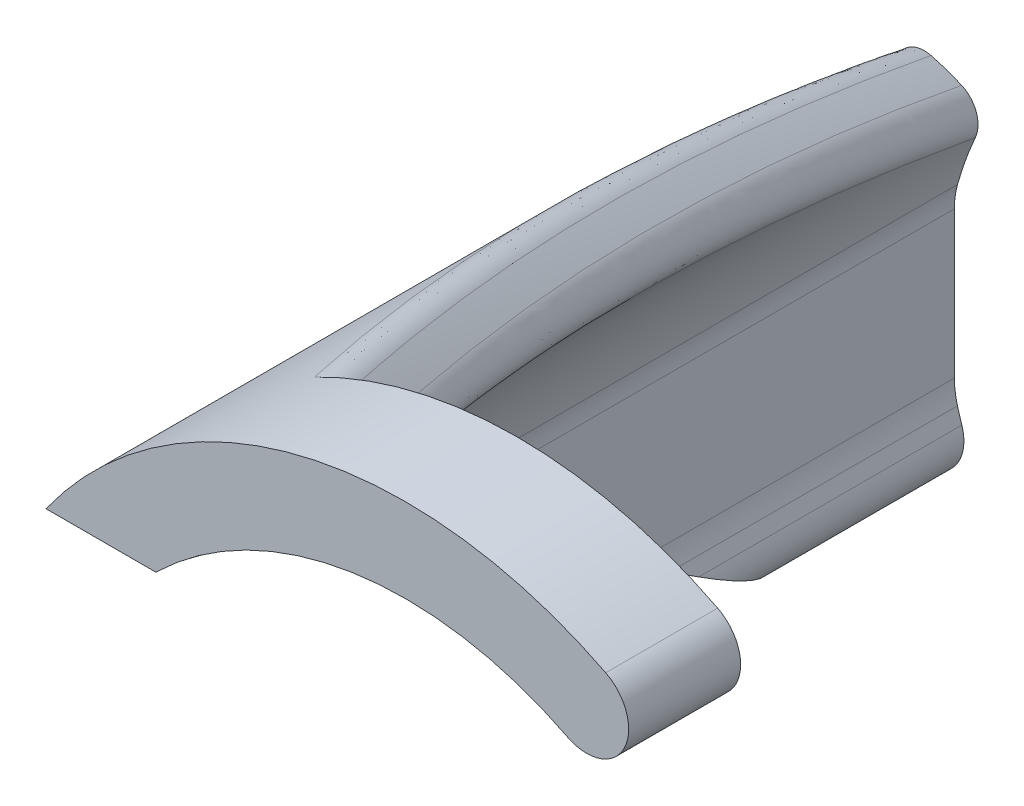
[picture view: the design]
ISO-10303-21;
HEADER;
FILE_DESCRIPTION(('STEP AP214'),'2;1');
FILE_NAME('part.step','',(''),(''),'','','');
FILE_SCHEMA(('AUTOMOTIVE_DESIGN { 1 0 10303 214 1 1 1 1 }'));
ENDSEC;
DATA;
#1=APPLICATION_CONTEXT('core data for automotive mechanical design processes');
#2=APPLICATION_PROTOCOL_DEFINITION('international standard','automotive_design',2000,#1);
#3=PRODUCT_CONTEXT('',#1,'mechanical');
#4=PRODUCT('Part','Part','',(#3));
#5=PRODUCT_RELATED_PRODUCT_CATEGORY('part','',(#4));
#6=PRODUCT_DEFINITION_FORMATION('','',#4);
#7=PRODUCT_DEFINITION_CONTEXT('part definition',#1,'design');
#8=PRODUCT_DEFINITION('design','',#6,#7);
#9=PRODUCT_DEFINITION_SHAPE('','',#8);
#10=(LENGTH_UNIT() NAMED_UNIT(*) SI_UNIT(.MILLI.,.METRE.));
#11=(NAMED_UNIT(*) PLANE_ANGLE_UNIT() SI_UNIT($,.RADIAN.));
#12=(NAMED_UNIT(*) SI_UNIT($,.STERADIAN.) SOLID_ANGLE_UNIT());
#13=UNCERTAINTY_MEASURE_WITH_UNIT(LENGTH_MEASURE(1.E-05),#10,'distance_accuracy_value','');
#14=(GEOMETRIC_REPRESENTATION_CONTEXT(3) GLOBAL_UNCERTAINTY_ASSIGNED_CONTEXT((#13)) GLOBAL_UNIT_ASSIGNED_CONTEXT((#10,
#11,#12)) REPRESENTATION_CONTEXT('',''));
#15=CARTESIAN_POINT('',(0.,0.,0.));
#16=DIRECTION('',(0.,0.,1.));
#17=DIRECTION('',(1.,0.,0.));
#18=AXIS2_PLACEMENT_3D('',#15,#16,#17);
#19=CARTESIAN_POINT('',(0.,0.,4.));
#20=DIRECTION('',(0.,0.,-1.));
#21=DIRECTION('',(-1.,0.,0.));
#22=AXIS2_PLACEMENT_3D('',#19,#20,#21);
#23=CYLINDRICAL_SURFACE('',#22,12.75);
#24=CARTESIAN_POINT('',(0.,0.,-11.774851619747));
#25=DIRECTION('',(0.,0.866025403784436,-0.500000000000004));
#26=DIRECTION('',(0.,-0.500000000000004,-0.866025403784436));
#27=AXIS2_PLACEMENT_3D('',#24,#25,#26);
#28=ELLIPSE('',#27,25.4999999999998,12.75);
#29=CARTESIAN_POINT('',(-8.92265947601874,9.10761482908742,4.));
#30=VERTEX_POINT('',#29);
#31=CARTESIAN_POINT('',(-12.2818902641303,3.42310846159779,-5.84585384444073));
#32=VERTEX_POINT('',#31);
#33=EDGE_CURVE('E165',#30,#32,#28,.F.);
#34=ORIENTED_EDGE('',*,*,#33,.T.);
#35=DIRECTION('',(0.,0.,-1.));
#36=VECTOR('',#35,1.);
#37=CARTESIAN_POINT('',(-12.2818902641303,3.42310846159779,4.));
#38=LINE('',#37,#36);
#39=CARTESIAN_POINT('',(-12.2818902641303,3.42310846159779,-28.));
#40=VERTEX_POINT('',#39);
#41=EDGE_CURVE('E379',#32,#40,#38,.T.);
#42=ORIENTED_EDGE('',*,*,#41,.T.);
#43=CARTESIAN_POINT('',(0.,0.,-28.));
#44=DIRECTION('',(0.,0.,1.));
#45=DIRECTION('',(1.,0.,0.));
#46=AXIS2_PLACEMENT_3D('',#43,#44,#45);
#47=CIRCLE('',#46,12.75);
#48=CARTESIAN_POINT('',(-11.6434217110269,5.19550102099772,-28.));
#49=VERTEX_POINT('',#48);
#50=EDGE_CURVE('E362',#40,#49,#47,.F.);
#51=ORIENTED_EDGE('',*,*,#50,.T.);
#52=CARTESIAN_POINT('',(-12.5740199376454,5.46335959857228,-31.56670425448));
#53=CARTESIAN_POINT('',(-12.2137477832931,5.30670095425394,-31.5576052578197));
#54=CARTESIAN_POINT('',(-12.0528599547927,4.95999277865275,-31.4663402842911));
#55=CARTESIAN_POINT('',(-11.8919721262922,4.61328460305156,-31.3750753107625));
#56=CARTESIAN_POINT('',(-12.0165530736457,4.26203615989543,-31.2504764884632));
#57=CARTESIAN_POINT('',(-12.5091224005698,5.65492223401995,-30.9623493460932));
#58=CARTESIAN_POINT('',(-12.1440419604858,5.49706561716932,-30.9542964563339));
#59=CARTESIAN_POINT('',(-11.9833889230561,5.14458022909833,-30.863675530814));
#60=CARTESIAN_POINT('',(-11.8225110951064,4.79266980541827,-30.7711616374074));
#61=CARTESIAN_POINT('',(-11.9539251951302,4.43858525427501,-30.6461215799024));
#62=CARTESIAN_POINT('',(-12.4391462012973,5.84425664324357,-30.3578893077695));
#63=CARTESIAN_POINT('',(-12.0698164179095,5.68464141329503,-30.3518125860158));
#64=CARTESIAN_POINT('',(-11.9096982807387,5.32687419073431,-30.2608507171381));
#65=CARTESIAN_POINT('',(-11.7493473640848,4.96963955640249,-30.168101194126));
#66=CARTESIAN_POINT('',(-11.8875210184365,4.6134826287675,-30.0416615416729));
#67=CARTESIAN_POINT('',(-12.2894975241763,6.21867938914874,-29.1488884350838));
#68=CARTESIAN_POINT('',(-11.9123950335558,6.05518332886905,-29.1465279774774));
#69=CARTESIAN_POINT('',(-11.7540277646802,5.68708166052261,-29.0550414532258));
#70=CARTESIAN_POINT('',(-11.5954236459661,5.31953410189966,-28.9617048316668));
#71=CARTESIAN_POINT('',(-11.7471739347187,4.95998040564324,-28.8326606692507));
#72=CARTESIAN_POINT('',(-12.2098250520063,6.40376772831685,-28.5443476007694));
#73=CARTESIAN_POINT('',(-11.8291931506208,6.23808584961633,-28.5438877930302));
#74=CARTESIAN_POINT('',(-11.6720478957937,5.8649951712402,-28.4520570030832));
#75=CARTESIAN_POINT('',(-11.514661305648,5.49239977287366,-28.3585297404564));
#76=CARTESIAN_POINT('',(-11.6732310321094,5.13158080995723,-28.2281198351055));
#77=CARTESIAN_POINT('',(-12.041268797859,6.76985681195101,-27.3354860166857));
#78=CARTESIAN_POINT('',(-11.6541217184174,6.59951067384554,-27.3386191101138));
#79=CARTESIAN_POINT('',(-11.4999733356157,6.21659841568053,-27.2462599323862));
#80=CARTESIAN_POINT('',(-11.3455842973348,5.83417573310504,-27.1522197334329));
#81=CARTESIAN_POINT('',(-11.5178424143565,5.47144292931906,-27.019258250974));
#82=CARTESIAN_POINT('',(-11.9523876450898,6.950858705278,-26.7311652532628));
#83=CARTESIAN_POINT('',(-11.5622467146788,6.77798805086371,-26.73610361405));
#84=CARTESIAN_POINT('',(-11.4098809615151,6.39028933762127,-26.6434473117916));
#85=CARTESIAN_POINT('',(-11.2572664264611,6.00304400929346,-26.5491979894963));
#86=CARTESIAN_POINT('',(-11.4363988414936,5.63970558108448,-26.4149374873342));
#87=CARTESIAN_POINT('',(-11.7656723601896,7.30879528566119,-25.5226635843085));
#88=CARTESIAN_POINT('',(-11.3699882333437,7.13061086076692,-25.5310844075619));
#89=CARTESIAN_POINT('',(-11.2216631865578,6.73347997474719,-25.4379345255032));
#90=CARTESIAN_POINT('',(-11.0730887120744,6.33680412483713,-25.3431866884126));
#91=CARTESIAN_POINT('',(-11.266007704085,5.97281942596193,-25.2064358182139));
#92=CARTESIAN_POINT('',(-11.6678382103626,7.48572996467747,-24.9184826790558));
#93=CARTESIAN_POINT('',(-11.269595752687,7.30471985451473,-24.928665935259));
#94=CARTESIAN_POINT('',(-11.1235377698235,6.90297968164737,-24.8352343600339));
#95=CARTESIAN_POINT('',(-10.9772218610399,6.50166180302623,-24.7402824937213));
#96=CARTESIAN_POINT('',(-11.1770601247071,6.13767061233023,-24.6022549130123));
#97=CARTESIAN_POINT('',(-11.3755205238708,7.98584177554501,-23.1906919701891));
#98=CARTESIAN_POINT('',(-10.9701603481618,7.79696139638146,-23.2038869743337));
#99=CARTESIAN_POINT('',(-10.8315106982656,7.3816710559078,-23.1116639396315));
#100=CARTESIAN_POINT('',(-10.6919623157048,6.96785485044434,-23.0141327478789));
#101=CARTESIAN_POINT('',(-10.9119416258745,6.60407378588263,-22.8744642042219));
#102=CARTESIAN_POINT('',(-11.1702905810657,8.30389578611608,-22.0673265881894));
#103=CARTESIAN_POINT('',(-10.7610991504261,8.10901153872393,-22.083833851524));
#104=CARTESIAN_POINT('',(-10.6278292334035,7.68560629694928,-21.9910252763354));
#105=CARTESIAN_POINT('',(-10.4935901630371,7.2635236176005,-21.8932136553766));
#106=CARTESIAN_POINT('',(-10.7265570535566,6.90123596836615,-21.751098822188));
#107=CARTESIAN_POINT('',(-10.730491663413,8.92436345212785,-19.8214468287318));
#108=CARTESIAN_POINT('',(-10.3146785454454,8.71688757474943,-19.8443045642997));
#109=CARTESIAN_POINT('',(-10.193346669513,8.27756871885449,-19.7506421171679));
#110=CARTESIAN_POINT('',(-10.0710428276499,7.83957197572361,-19.6519734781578));
#111=CARTESIAN_POINT('',(-10.3299578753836,7.48185059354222,-19.5052190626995));
#112=CARTESIAN_POINT('',(-10.4959146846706,9.22677280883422,-18.6989327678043));
#113=CARTESIAN_POINT('',(-10.0772302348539,9.01257370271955,-18.7250613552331));
#114=CARTESIAN_POINT('',(-9.96253817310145,8.56559152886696,-18.6308979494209));
#115=CARTESIAN_POINT('',(-9.84678817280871,8.1198195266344,-18.5318856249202));
#116=CARTESIAN_POINT('',(-10.1187362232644,7.76529926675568,-18.3827050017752));
#117=CARTESIAN_POINT('',(-9.98863708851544,9.82525693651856,-16.4127880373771));
#118=CARTESIAN_POINT('',(-9.56499845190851,9.59688269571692,-16.4453245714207));
#119=CARTESIAN_POINT('',(-9.46494474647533,9.13459376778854,-16.3505015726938));
#120=CARTESIAN_POINT('',(-9.36374599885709,8.67361377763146,-16.250431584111));
#121=CARTESIAN_POINT('',(-9.66214870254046,8.3271453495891,-16.0965602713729));
#122=CARTESIAN_POINT('',(-9.71482671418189,10.1206546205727,-15.2492153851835));
#123=CARTESIAN_POINT('',(-9.28907993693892,9.88464049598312,-15.2852130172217));
#124=CARTESIAN_POINT('',(-9.19712619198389,9.41488994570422,-15.1899113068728));
#125=CARTESIAN_POINT('',(-9.10391746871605,8.94634030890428,-15.0894478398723));
#126=CARTESIAN_POINT('',(-9.41579054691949,8.60494178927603,-14.9329876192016));
#127=CARTESIAN_POINT('',(-9.13689995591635,10.6902748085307,-12.9241721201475));
#128=CARTESIAN_POINT('',(-8.70787873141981,10.4384983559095,-12.967169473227));
#129=CARTESIAN_POINT('',(-8.63315791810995,9.95424821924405,-12.870999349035));
#130=CARTESIAN_POINT('',(-8.5571772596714,9.47120224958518,-12.7696505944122));
#131=CARTESIAN_POINT('',(-8.89569120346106,9.14159691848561,-12.6079443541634));
#132=CARTESIAN_POINT('',(-8.83278524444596,10.9644984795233,-11.7627013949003));
#133=CARTESIAN_POINT('',(-8.40247816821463,10.7044911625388,-11.8092950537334));
#134=CARTESIAN_POINT('',(-8.33700976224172,10.2133114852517,-11.7126775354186));
#135=CARTESIAN_POINT('',(-8.27015708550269,9.72323572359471,-11.6108946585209));
#136=CARTESIAN_POINT('',(-8.62195152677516,9.40045665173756,-11.4464736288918));
#137=CARTESIAN_POINT('',(-8.19488872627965,11.4890444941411,-9.44279036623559));
#138=CARTESIAN_POINT('',(-7.76295062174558,11.2121451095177,-9.49678566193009));
#139=CARTESIAN_POINT('',(-7.71696544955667,10.7075952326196,-9.39928502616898));
#140=CARTESIAN_POINT('',(-7.66959124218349,10.2041522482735,-9.29660251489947));
#141=CARTESIAN_POINT('',(-8.04748037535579,9.89669443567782,-9.12656260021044));
#142=CARTESIAN_POINT('',(-7.86112103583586,11.7393780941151,-8.28434888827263));
#143=CARTESIAN_POINT('',(-7.42870328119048,11.4537125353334,-8.34214556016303));
#144=CARTESIAN_POINT('',(-7.39308249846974,10.9428269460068,-8.24421305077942));
#145=CARTESIAN_POINT('',(-7.35593435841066,10.4329461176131,-8.14106108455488));
#146=CARTESIAN_POINT('',(-7.74676174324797,10.1340826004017,-7.96812112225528));
#147=CARTESIAN_POINT('',(-7.16416384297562,12.2134550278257,-5.9700154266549));
#148=CARTESIAN_POINT('',(-6.7317592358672,11.9098650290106,-6.03573662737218));
#149=CARTESIAN_POINT('',(-6.71782893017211,11.3868623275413,-5.93690101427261));
#150=CARTESIAN_POINT('',(-6.70236329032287,10.8648688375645,-5.83281977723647));
#151=CARTESIAN_POINT('',(-7.11843056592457,10.5848955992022,-5.65378766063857));
#152=CARTESIAN_POINT('',(-6.80096326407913,12.437188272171,-4.81412457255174));
#153=CARTESIAN_POINT('',(-6.36890443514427,12.1243283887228,-4.88392368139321));
#154=CARTESIAN_POINT('',(-6.36644796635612,11.5956559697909,-4.78466218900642));
#155=CARTESIAN_POINT('',(-6.36230293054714,11.0678818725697,-4.68007559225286));
#156=CARTESIAN_POINT('',(-6.79080789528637,10.7983113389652,-4.49789680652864));
#157=CARTESIAN_POINT('',(-6.04118170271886,12.8572289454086,-2.49184219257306));
#158=CARTESIAN_POINT('',(-5.61084251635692,12.5253800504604,-2.57021888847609));
#159=CARTESIAN_POINT('',(-5.63244895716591,11.9859337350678,-2.47007920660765));
#160=CARTESIAN_POINT('',(-5.65231717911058,11.4474111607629,-2.36445865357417));
#161=CARTESIAN_POINT('',(-6.10501027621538,11.2005044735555,-2.17561442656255));
#162=CARTESIAN_POINT('',(-5.64424747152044,13.0531683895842,-1.32549464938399));
#163=CARTESIAN_POINT('',(-5.21514791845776,12.7114576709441,-1.40835384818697));
#164=CARTESIAN_POINT('',(-5.24950205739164,12.1670535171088,-1.30778331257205));
#165=CARTESIAN_POINT('',(-5.28194266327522,11.6234421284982,-1.20161202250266));
#166=CARTESIAN_POINT('',(-5.74651129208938,11.388949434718,-1.00926688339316));
#167=CARTESIAN_POINT('',(-4.82153004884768,13.4105208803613,1.00281868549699));
#168=CARTESIAN_POINT('',(-4.39607508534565,13.0487854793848,0.910423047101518));
#169=CARTESIAN_POINT('',(-4.4568958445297,12.4952246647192,1.01198562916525));
#170=CARTESIAN_POINT('',(-4.51579362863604,11.9424595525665,1.11917599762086));
#171=CARTESIAN_POINT('',(-5.00298034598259,11.734597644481,1.31904645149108));
#172=CARTESIAN_POINT('',(-4.39574590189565,13.5719327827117,2.1647843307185));
#173=CARTESIAN_POINT('',(-3.97250912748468,13.1998865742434,2.06745825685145));
#174=CARTESIAN_POINT('',(-4.04723564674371,12.642274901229,2.16945851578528));
#175=CARTESIAN_POINT('',(-4.11984594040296,12.0853044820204,2.27724110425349));
#176=CARTESIAN_POINT('',(-4.61794750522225,11.891799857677,2.48101209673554));
#177=CARTESIAN_POINT('',(-3.51641356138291,13.8557709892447,4.48257580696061));
#178=CARTESIAN_POINT('',(-3.09891116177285,13.4628738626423,4.37467419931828));
#179=CARTESIAN_POINT('',(-3.20241901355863,12.8980438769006,4.47772214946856));
#180=CARTESIAN_POINT('',(-3.30380273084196,12.333856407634,4.58657356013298));
#181=CARTESIAN_POINT('',(-3.82228792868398,12.1708771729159,4.79880357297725));
#182=CARTESIAN_POINT('',(-3.06288450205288,13.9782238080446,5.63840528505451));
#183=CARTESIAN_POINT('',(-2.64869035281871,13.5746113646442,5.52501922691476));
#184=CARTESIAN_POINT('',(-2.76728015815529,13.0067886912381,5.62851691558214));
#185=CARTESIAN_POINT('',(-2.88353334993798,12.439422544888,5.73800562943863));
#186=CARTESIAN_POINT('',(-3.41167882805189,12.2927762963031,5.95463305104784));
#187=CARTESIAN_POINT('',(-2.12871788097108,14.1792873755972,7.9436459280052));
#188=CARTESIAN_POINT('',(-1.72261060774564,13.7540944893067,7.81840571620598));
#189=CARTESIAN_POINT('',(-1.87236283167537,13.1813107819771,7.92300839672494));
#190=CARTESIAN_POINT('',(-2.01976578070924,12.608984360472,8.03363426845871));
#191=CARTESIAN_POINT('',(-2.56543236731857,12.4968211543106,8.25987369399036));
#192=CARTESIAN_POINT('',(-1.64807812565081,14.2578945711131,9.09305656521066));
#193=CARTESIAN_POINT('',(-1.24652332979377,13.8216226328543,8.9616341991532));
#194=CARTESIAN_POINT('',(-1.41258236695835,13.2470845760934,9.06670452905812));
#195=CARTESIAN_POINT('',(-1.57605827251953,12.6727745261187,9.17801844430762));
#196=CARTESIAN_POINT('',(-2.12979298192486,12.5789636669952,9.40928433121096));
#197=CARTESIAN_POINT('',(-0.656422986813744,14.365859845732,11.3943473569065));
#198=CARTESIAN_POINT('',(-0.265693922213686,13.9073073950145,11.2494558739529));
#199=CARTESIAN_POINT('',(-0.465565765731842,13.3304481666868,11.3556518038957));
#200=CARTESIAN_POINT('',(-0.662791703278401,12.7538212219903,11.46824277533));
#201=CARTESIAN_POINT('',(-1.23050406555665,12.6986632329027,11.710575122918));
#202=CARTESIAN_POINT('',(-0.145168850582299,14.3947582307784,12.5461529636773));
#203=CARTESIAN_POINT('',(0.239501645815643,13.9247308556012,12.3941313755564));
#204=CARTESIAN_POINT('',(0.0218840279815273,13.3475891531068,12.500820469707));
#205=CARTESIAN_POINT('',(-0.192822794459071,12.770386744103,12.6141666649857));
#206=CARTESIAN_POINT('',(-0.766633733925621,12.735803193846,12.8623807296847));
#207=CARTESIAN_POINT('',(0.901885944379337,14.3946670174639,14.8392096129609));
#208=CARTESIAN_POINT('',(1.27240630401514,13.9018587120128,14.6715130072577));
#209=CARTESIAN_POINT('',(1.01823940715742,13.3256009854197,14.7794814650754));
#210=CARTESIAN_POINT('',(0.766998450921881,12.7492751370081,14.8941414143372));
#211=CARTESIAN_POINT('',(0.183849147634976,12.7575363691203,15.1554373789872));
#212=CARTESIAN_POINT('',(1.43767962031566,14.3656937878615,15.9804635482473));
#213=CARTESIAN_POINT('',(1.80039228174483,13.8612361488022,15.8044842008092));
#214=CARTESIAN_POINT('',(1.52713888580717,13.2864877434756,15.912977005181));
#215=CARTESIAN_POINT('',(1.25710226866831,12.711290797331,16.0284582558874));
#216=CARTESIAN_POINT('',(0.670455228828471,12.7421444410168,16.2966913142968));
#217=CARTESIAN_POINT('',(2.25898434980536,14.2720539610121,17.684192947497));
#218=CARTESIAN_POINT('',(2.60688374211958,13.7506468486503,17.4917892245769));
#219=CARTESIAN_POINT('',(2.30540850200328,13.1792838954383,17.6039447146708));
#220=CARTESIAN_POINT('',(2.00474613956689,12.6078117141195,17.7178667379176));
#221=CARTESIAN_POINT('',(1.4167004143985,12.6735168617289,18.0004207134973));
#222=CARTESIAN_POINT('',(2.53618825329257,14.2323638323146,18.2517288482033));
#223=CARTESIAN_POINT('',(2.8793058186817,13.7052165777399,18.0545363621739));
#224=CARTESIAN_POINT('',(2.56779012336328,13.1353407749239,18.1670306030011));
#225=CARTESIAN_POINT('',(2.25712674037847,12.5652956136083,18.2813323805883));
#226=CARTESIAN_POINT('',(1.66862614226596,12.6429575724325,18.5679566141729));
#227=CARTESIAN_POINT('',(3.09581623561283,14.1348184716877,19.3829335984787));
#228=CARTESIAN_POINT('',(3.42872641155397,13.59632235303,19.1756756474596));
#229=CARTESIAN_POINT('',(3.0968157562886,13.0299510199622,19.2889013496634));
#230=CARTESIAN_POINT('',(2.76576022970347,12.4634088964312,19.4039403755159));
#231=CARTESIAN_POINT('',(2.17733145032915,12.5653468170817,19.6991613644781));
#232=CARTESIAN_POINT('',(3.37824001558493,14.0769642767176,19.9466026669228));
#233=CARTESIAN_POINT('',(3.70576531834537,13.5327959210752,19.7341066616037));
#234=CARTESIAN_POINT('',(3.36345952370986,12.9685053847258,19.8476864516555));
#235=CARTESIAN_POINT('',(3.02204935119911,12.4039798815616,19.9631217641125));
#236=CARTESIAN_POINT('',(2.43411075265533,12.5182962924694,20.2628304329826));
#237=CARTESIAN_POINT('',(3.94814966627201,13.9415442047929,21.0700593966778));
#238=CARTESIAN_POINT('',(4.26418443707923,13.386215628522,20.8465226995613));
#239=CARTESIAN_POINT('',(3.90075807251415,12.826681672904,20.9608656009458));
#240=CARTESIAN_POINT('',(3.5382320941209,12.2669086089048,21.0770739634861));
#241=CARTESIAN_POINT('',(2.95237879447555,12.4063046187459,21.3862871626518));
#242=CARTESIAN_POINT('',(4.23564024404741,13.863958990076,21.6298426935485));
#243=CARTESIAN_POINT('',(4.54560987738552,13.303070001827,21.4005409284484));
#244=CARTESIAN_POINT('',(4.17141654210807,12.7462850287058,21.5152547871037));
#245=CARTESIAN_POINT('',(3.79816574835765,12.1891807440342,21.6318782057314));
#246=CARTESIAN_POINT('',(3.21387191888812,12.3413459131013,21.9460704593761));
#247=CARTESIAN_POINT('',(4.8148877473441,13.6873160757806,22.7443127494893));
#248=CARTESIAN_POINT('',(5.11191579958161,13.1156040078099,22.5028205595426));
#249=CARTESIAN_POINT('',(4.71586475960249,12.5649684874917,22.6183362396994));
#250=CARTESIAN_POINT('',(4.32075943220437,12.0140234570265,22.7357680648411));
#251=CARTESIAN_POINT('',(3.74084259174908,12.1919364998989,23.060540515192));
#252=CARTESIAN_POINT('',(5.1066455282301,13.5882540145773,23.2989984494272));
#253=CARTESIAN_POINT('',(5.39684005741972,13.0111953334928,23.0511211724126));
#254=CARTESIAN_POINT('',(4.98965513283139,12.4640444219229,23.1670273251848));
#255=CARTESIAN_POINT('',(4.58345815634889,11.9165118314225,23.2848931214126));
#256=CARTESIAN_POINT('',(4.00632093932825,12.1074818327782,23.6152262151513));
#257=CARTESIAN_POINT('',(5.40021582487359,13.4775744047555,23.8506943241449));
#258=CARTESIAN_POINT('',(5.68261146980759,12.8955515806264,23.5950741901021));
#259=CARTESIAN_POINT('',(5.26464476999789,12.3520607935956,23.7123820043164));
#260=CARTESIAN_POINT('',(4.84667807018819,11.8085700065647,23.8296898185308));
#261=CARTESIAN_POINT('',(4.27349910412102,12.012481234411,24.1669220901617));
#262=(BOUNDED_SURFACE() B_SPLINE_SURFACE(3,2,((#52,#53,#54,#55,#56),(#57,#58,#59,#60,#61),(#62,
#63,#64,#65,#66),(#67,#68,#69,#70,#71),(#72,#73,#74,#75,#76),(#77,#78,#79,#80,#81),(#82,#83,#84,
#85,#86),(#87,#88,#89,#90,#91),(#92,#93,#94,#95,#96),(#97,#98,#99,#100,#101),(#102,#103,#104,
#105,#106),(#107,#108,#109,#110,#111),(#112,#113,#114,#115,#116),(#117,#118,#119,#120,#121),
(#122,#123,#124,#125,#126),(#127,#128,#129,#130,#131),(#132,#133,#134,#135,#136),(#137,#138,
#139,#140,#141),(#142,#143,#144,#145,#146),(#147,#148,#149,#150,#151),(#152,#153,#154,#155,
#156),(#157,#158,#159,#160,#161),(#162,#163,#164,#165,#166),(#167,#168,#169,#170,#171),(#172,
#173,#174,#175,#176),(#177,#178,#179,#180,#181),(#182,#183,#184,#185,#186),(#187,#188,#189,#190,
#191),(#192,#193,#194,#195,#196),(#197,#198,#199,#200,#201),(#202,#203,#204,#205,#206),(#207,
#208,#209,#210,#211),(#212,#213,#214,#215,#216),(#217,#218,#219,#220,#221),(#222,#223,#224,#225,
#226),(#227,#228,#229,#230,#231),(#232,#233,#234,#235,#236),(#237,#238,#239,#240,#241),(#242,
#243,#244,#245,#246),(#247,#248,#249,#250,#251),(#252,#253,#254,#255,#256),(#257,#258,#259,#260,
#261)),.UNSPECIFIED.,.F.,.F.,.F.) B_SPLINE_SURFACE_WITH_KNOTS((4,2,2,2,2,2,2,2,2,2,2,2,2,2,2,2,
2,2,2,2,4),(3,2,3),(0.,1.91166132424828,3.82332152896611,5.73443742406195,7.64555709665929,
11.2006112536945,14.7566371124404,18.4477547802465,22.1386688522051,25.8278351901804,
29.518396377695,33.2539924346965,36.9897122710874,40.7228842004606,44.4563586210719,
48.2241772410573,51.9909302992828,53.8809245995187,55.770811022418,57.6625568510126,
59.5546872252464),(0.,0.5,1.),
.UNSPECIFIED.) GEOMETRIC_REPRESENTATION_ITEM() RATIONAL_B_SPLINE_SURFACE(((1.,0.930717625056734,
1.,0.930717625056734,1.),(1.,0.929178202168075,1.,0.929178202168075,1.),(1.,0.927719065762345,
1.,0.927719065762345,1.),(1.,0.924924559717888,1.,0.924924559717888,1.),(1.,0.923589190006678,
1.,0.923589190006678,1.),(1.,0.921005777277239,1.,0.921005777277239,1.),(1.,0.919757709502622,
1.,0.919757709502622,1.),(1.,0.917326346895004,1.,0.917326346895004,1.),(1.,0.916143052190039,
1.,0.916143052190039,1.),(1.,0.912826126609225,1.,0.912826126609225,1.),(1.,0.910750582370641,
1.,0.910750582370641,1.),(1.,0.906690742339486,1.,0.906690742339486,1.),(1.,0.904706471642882,
1.,0.904706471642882,1.),(1.,0.900711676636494,1.,0.900711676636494,1.),(1.,0.898703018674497,
1.,0.898703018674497,1.),(1.,0.894704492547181,1.,0.894704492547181,1.),(1.,0.892714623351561,
1.,0.892714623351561,1.),(1.,0.88873065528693,1.,0.88873065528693,1.),(1.,0.886736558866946,1.,
0.886736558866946,1.),(1.,0.882723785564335,1.,0.882723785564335,1.),(1.,0.880705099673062,1.,
0.880705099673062,1.),(1.,0.876603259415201,1.,0.876603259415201,1.),(1.,0.874519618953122,1.,
0.874519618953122,1.),(1.,0.870296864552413,1.,0.870296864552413,1.),(1.,0.868157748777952,1.,
0.868157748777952,1.),(1.,0.863811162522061,1.,0.863811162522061,1.),(1.,0.861603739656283,1.,
0.861603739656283,1.),(1.,0.857104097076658,1.,0.857104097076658,1.),(1.,0.854811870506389,1.,
0.854811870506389,1.),(1.,0.850105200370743,1.,0.850105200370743,1.),(1.,0.847689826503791,1.,
0.847689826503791,1.),(1.,0.842738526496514,1.,0.842738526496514,1.),(1.,0.840202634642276,1.,
0.840202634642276,1.),(1.,0.836287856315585,1.,0.836287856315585,1.),(1.,0.834962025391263,1.,
0.834962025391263,1.),(1.,0.832271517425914,1.,0.832271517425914,1.),(1.,0.830906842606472,1.,
0.830906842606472,1.),(1.,0.828134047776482,1.,0.828134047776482,1.),(1.,0.826725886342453,1.,
0.826725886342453,1.),(1.,0.823863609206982,1.,0.823863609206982,1.),(1.,0.822409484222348,1.,
0.822409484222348,1.),(1.,0.820930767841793,1.,0.820930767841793,1.))) REPRESENTATION_ITEM('') SURFACE());
#263=CARTESIAN_POINT('',(-12.0165530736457,4.26203615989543,-31.2504764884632));
#264=CARTESIAN_POINT('',(-11.9539251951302,4.43858525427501,-30.6461215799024));
#265=CARTESIAN_POINT('',(-11.8875210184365,4.6134826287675,-30.0416615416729));
#266=CARTESIAN_POINT('',(-11.7471739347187,4.95998040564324,-28.8326606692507));
#267=CARTESIAN_POINT('',(-11.6732310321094,5.13158080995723,-28.2281198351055));
#268=CARTESIAN_POINT('',(-11.5178424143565,5.47144292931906,-27.019258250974));
#269=CARTESIAN_POINT('',(-11.4363988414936,5.63970558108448,-26.4149374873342));
#270=CARTESIAN_POINT('',(-11.266007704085,5.97281942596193,-25.2064358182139));
#271=CARTESIAN_POINT('',(-11.1770601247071,6.13767061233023,-24.6022549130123));
#272=CARTESIAN_POINT('',(-10.9119416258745,6.60407378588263,-22.8744642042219));
#273=CARTESIAN_POINT('',(-10.7265570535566,6.90123596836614,-21.751098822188));
#274=CARTESIAN_POINT('',(-10.3299578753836,7.48185059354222,-19.5052190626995));
#275=CARTESIAN_POINT('',(-10.1187362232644,7.76529926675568,-18.3827050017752));
#276=CARTESIAN_POINT('',(-9.66214870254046,8.3271453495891,-16.0965602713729));
#277=CARTESIAN_POINT('',(-9.41579054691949,8.60494178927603,-14.9329876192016));
#278=CARTESIAN_POINT('',(-8.89569120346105,9.14159691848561,-12.6079443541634));
#279=CARTESIAN_POINT('',(-8.62195152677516,9.40045665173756,-11.4464736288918));
#280=CARTESIAN_POINT('',(-8.04748037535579,9.89669443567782,-9.12656260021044));
#281=CARTESIAN_POINT('',(-7.74676174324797,10.1340826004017,-7.96812112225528));
#282=CARTESIAN_POINT('',(-7.11843056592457,10.5848955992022,-5.65378766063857));
#283=CARTESIAN_POINT('',(-6.79080789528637,10.7983113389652,-4.49789680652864));
#284=CARTESIAN_POINT('',(-6.10501027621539,11.2005044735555,-2.17561442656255));
#285=CARTESIAN_POINT('',(-5.74651129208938,11.388949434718,-1.00926688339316));
#286=CARTESIAN_POINT('',(-5.00298034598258,11.734597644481,1.31904645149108));
#287=CARTESIAN_POINT('',(-4.61794750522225,11.891799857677,2.48101209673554));
#288=CARTESIAN_POINT('',(-3.82228792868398,12.1708771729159,4.79880357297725));
#289=CARTESIAN_POINT('',(-3.41167882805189,12.2927762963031,5.95463305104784));
#290=CARTESIAN_POINT('',(-2.56543236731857,12.4968211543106,8.25987369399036));
#291=CARTESIAN_POINT('',(-2.12979298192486,12.5789636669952,9.40928433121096));
#292=CARTESIAN_POINT('',(-1.23050406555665,12.6986632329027,11.710575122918));
#293=CARTESIAN_POINT('',(-0.766633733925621,12.735803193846,12.8623807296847));
#294=CARTESIAN_POINT('',(0.183849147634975,12.7575363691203,15.1554373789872));
#295=CARTESIAN_POINT('',(0.670455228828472,12.7421444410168,16.2966913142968));
#296=CARTESIAN_POINT('',(1.4167004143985,12.6735168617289,18.0004207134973));
#297=CARTESIAN_POINT('',(1.66862614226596,12.6429575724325,18.5679566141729));
#298=CARTESIAN_POINT('',(2.17733145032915,12.5653468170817,19.6991613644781));
#299=CARTESIAN_POINT('',(2.43411075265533,12.5182962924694,20.2628304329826));
#300=CARTESIAN_POINT('',(2.95237879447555,12.4063046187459,21.3862871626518));
#301=CARTESIAN_POINT('',(3.21387191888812,12.3413459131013,21.9460704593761));
#302=CARTESIAN_POINT('',(3.74084259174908,12.1919364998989,23.060540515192));
#303=CARTESIAN_POINT('',(4.00632093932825,12.1074818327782,23.6152262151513));
#304=CARTESIAN_POINT('',(4.27349910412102,12.012481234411,24.1669220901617));
#305=B_SPLINE_CURVE_WITH_KNOTS('',3,(#263,#264,#265,#266,#267,#268,#269,#270,#271,#272,#273,
#274,#275,#276,#277,#278,#279,#280,#281,#282,#283,#284,#285,#286,#287,#288,#289,#290,#291,#292,
#293,#294,#295,#296,#297,#298,#299,#300,#301,#302,#303,#304),.UNSPECIFIED.,.F.,.F.,(4,2,2,2,2,2,
2,2,2,2,2,2,2,2,2,2,2,2,2,2,4),(0.,1.91166132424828,3.82332152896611,5.73443742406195,
7.64555709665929,11.2006112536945,14.7566371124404,18.4477547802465,22.1386688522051,
25.8278351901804,29.518396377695,33.2539924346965,36.9897122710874,40.7228842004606,
44.4563586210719,48.2241772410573,51.9909302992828,53.8809245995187,55.770811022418,
57.6625568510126,59.5546872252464),.UNSPECIFIED.);
#306=CARTESIAN_POINT('',(-5.42412642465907,11.538689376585,0.));
#307=VERTEX_POINT('',#306);
#308=EDGE_CURVE('E298',#49,#307,#305,.T.);
#309=ORIENTED_EDGE('',*,*,#308,.T.);
#310=CARTESIAN_POINT('',(0.,0.,0.));
#311=DIRECTION('',(0.,0.,1.));
#312=DIRECTION('',(1.,0.,0.));
#313=AXIS2_PLACEMENT_3D('',#310,#311,#312);
#314=CIRCLE('',#313,12.75);
#315=CARTESIAN_POINT('',(5.78837887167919,11.3603331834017,0.));
#316=VERTEX_POINT('',#315);
#317=EDGE_CURVE('E190',#307,#316,#314,.F.);
#318=ORIENTED_EDGE('',*,*,#317,.T.);
#319=DIRECTION('',(0.,0.,-1.));
#320=VECTOR('',#319,1.);
#321=CARTESIAN_POINT('',(5.78837887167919,11.3603331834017,4.));
#322=LINE('',#321,#320);
#323=CARTESIAN_POINT('',(5.78837887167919,11.3603331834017,4.));
#324=VERTEX_POINT('',#323);
#325=EDGE_CURVE('E202',#324,#316,#322,.T.);
#326=ORIENTED_EDGE('',*,*,#325,.F.);
#327=CARTESIAN_POINT('',(0.,0.,4.));
#328=DIRECTION('',(0.,0.,1.));
#329=DIRECTION('',(1.,0.,0.));
#330=AXIS2_PLACEMENT_3D('',#327,#328,#329);
#331=CIRCLE('',#330,12.75);
#332=EDGE_CURVE('E185',#30,#324,#331,.F.);
#333=ORIENTED_EDGE('',*,*,#332,.F.);
#334=EDGE_LOOP('',(#34,#42,#51,#309,#318,#326,#333));
#335=FACE_BOUND('',#334,.T.);
#336=ADVANCED_FACE('F41',(#335),#23,.F.);
#337=CARTESIAN_POINT('',(0.,0.,4.));
#338=DIRECTION('',(0.,0.,-1.));
#339=DIRECTION('',(-1.,0.,0.));
#340=AXIS2_PLACEMENT_3D('',#337,#338,#339);
#341=CYLINDRICAL_SURFACE('',#340,15.75);
#342=CARTESIAN_POINT('',(0.,0.,-28.));
#343=DIRECTION('',(0.,0.,1.));
#344=DIRECTION('',(1.,0.,0.));
#345=AXIS2_PLACEMENT_3D('',#342,#343,#344);
#346=CIRCLE('',#345,15.75);
#347=CARTESIAN_POINT('',(-14.765625,5.48076804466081,-28.));
#348=VERTEX_POINT('',#347);
#349=CARTESIAN_POINT('',(-14.422335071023,6.32919829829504,-28.));
#350=VERTEX_POINT('',#349);
#351=EDGE_CURVE('E354',#348,#350,#346,.F.);
#352=ORIENTED_EDGE('',*,*,#351,.F.);
#353=DIRECTION('',(0.,0.,-1.));
#354=VECTOR('',#353,1.);
#355=CARTESIAN_POINT('',(-14.765625,5.48076804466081,4.));
#356=LINE('',#355,#354);
#357=CARTESIAN_POINT('',(-14.765625,5.4807680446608,-2.28188290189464));
#358=VERTEX_POINT('',#357);
#359=EDGE_CURVE('E178',#348,#358,#356,.F.);
#360=ORIENTED_EDGE('',*,*,#359,.T.);
#361=CARTESIAN_POINT('',(0.,0.,-11.774851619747));
#362=DIRECTION('',(0.,0.866025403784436,-0.500000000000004));
#363=DIRECTION('',(0.,-0.500000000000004,-0.866025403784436));
#364=AXIS2_PLACEMENT_3D('',#361,#362,#363);
#365=ELLIPSE('',#364,31.4999999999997,15.75);
#366=CARTESIAN_POINT('',(-12.849663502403,9.10761482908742,4.));
#367=VERTEX_POINT('',#366);
#368=EDGE_CURVE('E163',#367,#358,#365,.F.);
#369=ORIENTED_EDGE('',*,*,#368,.F.);
#370=CARTESIAN_POINT('',(0.,0.,4.));
#371=DIRECTION('',(0.,0.,1.));
#372=DIRECTION('',(1.,0.,0.));
#373=AXIS2_PLACEMENT_3D('',#370,#371,#372);
#374=CIRCLE('',#373,15.75);
#375=CARTESIAN_POINT('',(7.15035037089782,14.0333527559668,4.));
#376=VERTEX_POINT('',#375);
#377=EDGE_CURVE('E175',#367,#376,#374,.F.);
#378=ORIENTED_EDGE('',*,*,#377,.T.);
#379=DIRECTION('',(0.,0.,-1.));
#380=VECTOR('',#379,1.);
#381=CARTESIAN_POINT('',(7.15035037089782,14.0333527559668,4.));
#382=LINE('',#381,#380);
#383=CARTESIAN_POINT('',(7.15035037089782,14.0333527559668,0.));
#384=VERTEX_POINT('',#383);
#385=EDGE_CURVE('E197',#376,#384,#382,.T.);
#386=ORIENTED_EDGE('',*,*,#385,.T.);
#387=CARTESIAN_POINT('',(0.,0.,0.));
#388=DIRECTION('',(0.,0.,1.));
#389=DIRECTION('',(1.,0.,0.));
#390=AXIS2_PLACEMENT_3D('',#387,#388,#389);
#391=CIRCLE('',#390,15.75);
#392=CARTESIAN_POINT('',(-7.26053441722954,13.9766641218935,0.));
#393=VERTEX_POINT('',#392);
#394=EDGE_CURVE('E198',#393,#384,#391,.F.);
#395=ORIENTED_EDGE('',*,*,#394,.F.);
#396=CARTESIAN_POINT('',(-15.1270251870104,4.38584187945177,-33.7644915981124));
#397=CARTESIAN_POINT('',(-14.8827218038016,5.22845853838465,-34.0579170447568));
#398=CARTESIAN_POINT('',(-13.9779277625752,5.03711260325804,-34.0807193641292));
#399=CARTESIAN_POINT('',(-15.0591973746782,4.61977963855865,-33.0824569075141));
#400=CARTESIAN_POINT('',(-14.8048072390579,5.44873859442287,-33.3761714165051));
#401=CARTESIAN_POINT('',(-13.9102353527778,5.25535257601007,-33.3986846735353));
#402=CARTESIAN_POINT('',(-14.9858608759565,4.8524347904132,-32.4005280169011));
#403=CARTESIAN_POINT('',(-14.7213676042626,5.66910088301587,-32.6914414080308));
#404=CARTESIAN_POINT('',(-13.8369452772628,5.47226977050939,-32.7167557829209));
#405=CARTESIAN_POINT('',(-14.8281846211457,5.31480136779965,-31.0369058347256));
#406=CARTESIAN_POINT('',(-14.5441115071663,6.10708665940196,-31.3229262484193));
#407=CARTESIAN_POINT('',(-13.6794196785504,5.90312590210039,-31.3531336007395));
#408=CARTESIAN_POINT('',(-14.7438447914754,5.54451277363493,-30.3552125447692));
#409=CARTESIAN_POINT('',(-14.4503220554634,6.32488722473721,-30.6386532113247));
#410=CARTESIAN_POINT('',(-13.5951840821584,6.11706481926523,-30.6714403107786));
#411=CARTESIAN_POINT('',(-14.4743204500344,6.2287160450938,-28.3103650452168));
#412=CARTESIAN_POINT('',(-14.1545761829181,6.97073899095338,-28.5952228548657));
#413=CARTESIAN_POINT('',(-13.3264128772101,6.75396391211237,-28.6265928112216));
#414=CARTESIAN_POINT('',(-14.2726480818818,6.67821817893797,-26.9476140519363));
#415=CARTESIAN_POINT('',(-13.936112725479,7.39708534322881,-27.2274055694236));
#416=CARTESIAN_POINT('',(-13.125829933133,7.17195159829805,-27.26384181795));
#417=CARTESIAN_POINT('',(-13.8259020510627,7.55981121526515,-24.225881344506));
#418=CARTESIAN_POINT('',(-13.4581466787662,8.23162302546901,-24.4978819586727));
#419=CARTESIAN_POINT('',(-12.6832114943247,7.99087232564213,-24.5421091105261));
#420=CARTESIAN_POINT('',(-13.5808987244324,7.99192896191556,-22.8668970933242));
#421=CARTESIAN_POINT('',(-13.1990508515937,8.6405010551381,-23.1347581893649));
#422=CARTESIAN_POINT('',(-12.4412431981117,8.39183171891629,-23.1831248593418));
#423=CARTESIAN_POINT('',(-13.047532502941,8.83592444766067,-20.1510011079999));
#424=CARTESIAN_POINT('',(-12.6398216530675,9.43732629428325,-20.4120720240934));
#425=CARTESIAN_POINT('',(-11.9162215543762,9.17404272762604,-20.467228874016));
#426=CARTESIAN_POINT('',(-12.7591745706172,9.24780449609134,-18.7940891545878));
#427=CARTESIAN_POINT('',(-12.3400340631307,9.82581213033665,-19.0515518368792));
#428=CARTESIAN_POINT('',(-11.6331729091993,9.55529659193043,-19.1103169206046));
#429=CARTESIAN_POINT('',(-12.3068919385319,9.83142681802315,-16.8154399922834));
#430=CARTESIAN_POINT('',(-11.8712308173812,10.3766803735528,-17.0619019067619));
#431=CARTESIAN_POINT('',(-11.190420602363,10.09476886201,-17.1316677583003));
#432=CARTESIAN_POINT('',(-12.1599418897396,10.0126479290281,-16.19270979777));
#433=CARTESIAN_POINT('',(-11.719865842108,10.5470292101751,-16.4377860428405));
#434=CARTESIAN_POINT('',(-11.0467289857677,10.262168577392,-16.5089375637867));
#435=CARTESIAN_POINT('',(-11.85693763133,10.3696850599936,-14.9476154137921));
#436=CARTESIAN_POINT('',(-11.4085615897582,10.8822696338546,-15.1900372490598));
#437=CARTESIAN_POINT('',(-10.7507667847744,10.5917394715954,-15.2638431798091));
#438=CARTESIAN_POINT('',(-11.7008806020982,10.545499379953,-14.3252513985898));
#439=CARTESIAN_POINT('',(-11.248651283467,11.0472054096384,-14.5663416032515));
#440=CARTESIAN_POINT('',(-10.5984935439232,10.7539090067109,-14.6414791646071));
#441=CARTESIAN_POINT('',(-11.2041957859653,11.0802730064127,-12.4010614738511));
#442=CARTESIAN_POINT('',(-10.7423425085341,11.5468212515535,-12.64380239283));
#443=CARTESIAN_POINT('',(-10.114336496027,11.2467899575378,-12.7172892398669));
#444=CARTESIAN_POINT('',(-10.848298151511,11.4293314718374,-11.1002321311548));
#445=CARTESIAN_POINT('',(-10.3803022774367,11.8733031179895,-11.3401490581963));
#446=CARTESIAN_POINT('',(-9.76808334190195,11.5679432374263,-11.416459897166));
#447=CARTESIAN_POINT('',(-10.0973710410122,12.0978643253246,-8.5017846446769));
#448=CARTESIAN_POINT('',(-9.61927080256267,12.4964679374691,-8.73671055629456));
#449=CARTESIAN_POINT('',(-9.03881728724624,12.181768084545,-8.81801241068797));
#450=CARTESIAN_POINT('',(-9.7023406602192,12.4173380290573,-7.20416657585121));
#451=CARTESIAN_POINT('',(-9.2205538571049,12.7935583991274,-7.43649254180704));
#452=CARTESIAN_POINT('',(-8.6558035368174,12.4744389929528,-7.52039434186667));
#453=CARTESIAN_POINT('',(-8.87380983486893,13.0223284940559,-4.61322147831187));
#454=CARTESIAN_POINT('',(-8.38683478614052,13.3537501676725,-4.84091254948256));
#455=CARTESIAN_POINT('',(-7.85368529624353,13.0271612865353,-4.92944924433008));
#456=CARTESIAN_POINT('',(-8.44032211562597,13.3078564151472,-3.3198931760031));
#457=CARTESIAN_POINT('',(-7.95210540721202,13.6172771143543,-3.54517061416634));
#458=CARTESIAN_POINT('',(-7.43459274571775,13.2872233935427,-3.63612094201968));
#459=CARTESIAN_POINT('',(-7.53530797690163,13.8404260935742,-0.737575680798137));
#460=CARTESIAN_POINT('',(-7.04679243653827,14.1059875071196,-0.958538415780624));
#461=CARTESIAN_POINT('',(-6.56074783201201,13.7704275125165,-1.05380344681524));
#462=CARTESIAN_POINT('',(-7.06377311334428,14.0874592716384,0.551412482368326));
#463=CARTESIAN_POINT('',(-6.57644185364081,14.3315932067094,0.332705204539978));
#464=CARTESIAN_POINT('',(-6.10598755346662,13.9935612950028,0.235184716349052));
#465=CARTESIAN_POINT('',(-6.21510538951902,14.4772454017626,2.77861358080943));
#466=CARTESIAN_POINT('',(-5.73064730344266,14.6850192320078,2.56621875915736));
#467=CARTESIAN_POINT('',(-5.28840379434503,14.3435560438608,2.46238581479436));
#468=CARTESIAN_POINT('',(-5.84658779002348,14.6301940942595,3.71815198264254));
#469=CARTESIAN_POINT('',(-5.36448528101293,14.8227176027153,3.5072536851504));
#470=CARTESIAN_POINT('',(-4.93364947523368,14.4801847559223,3.40192421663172));
#471=CARTESIAN_POINT('',(-5.09007787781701,14.9102755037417,5.59376497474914));
#472=CARTESIAN_POINT('',(-4.61388205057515,15.0726335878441,5.38566476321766));
#473=CARTESIAN_POINT('',(-4.20591017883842,14.7287268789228,5.27753720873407));
#474=CARTESIAN_POINT('',(-4.70208528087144,15.0374078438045,6.52983951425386));
#475=CARTESIAN_POINT('',(-4.22952113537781,15.1850349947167,6.32316945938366));
#476=CARTESIAN_POINT('',(-3.83292493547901,14.8406399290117,6.21361174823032));
#477=CARTESIAN_POINT('',(-3.90726374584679,15.2632375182,8.39759312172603));
#478=CARTESIAN_POINT('',(-3.4431465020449,15.3818377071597,8.19359577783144));
#479=CARTESIAN_POINT('',(-3.06933568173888,15.037263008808,8.08136535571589));
#480=CARTESIAN_POINT('',(-3.50044174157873,15.3619452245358,9.32927367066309));
#481=CARTESIAN_POINT('',(-3.0412137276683,15.4664414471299,9.12664478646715));
#482=CARTESIAN_POINT('',(-2.67873815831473,15.1219829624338,9.01304590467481));
#483=CARTESIAN_POINT('',(-2.66843345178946,15.52810137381,11.1878683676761));
#484=CARTESIAN_POINT('',(-2.22015657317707,15.6049190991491,10.9877901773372));
#485=CARTESIAN_POINT('',(-1.88037389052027,15.2615280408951,10.8716406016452));
#486=CARTESIAN_POINT('',(-2.24324773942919,15.5955507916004,12.1147826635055));
#487=CARTESIAN_POINT('',(-1.80109846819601,15.6589960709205,11.9160161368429));
#488=CARTESIAN_POINT('',(-1.47260768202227,15.3163540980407,11.7985548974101));
#489=CARTESIAN_POINT('',(-1.37281047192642,15.6962073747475,13.9681733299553));
#490=CARTESIAN_POINT('',(-0.944124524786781,15.7334718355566,13.7718192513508));
#491=CARTESIAN_POINT('',(-0.638270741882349,15.3932158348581,13.6519455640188));
#492=CARTESIAN_POINT('',(-0.927460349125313,15.7292217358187,14.8946185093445));
#493=CARTESIAN_POINT('',(-0.506159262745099,15.7538988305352,14.6995315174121));
#494=CARTESIAN_POINT('',(-0.211607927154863,15.4150671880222,14.578390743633));
#495=CARTESIAN_POINT('',(-0.0199101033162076,15.7565288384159,16.7406412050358));
#496=CARTESIAN_POINT('',(0.385476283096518,15.7567986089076,16.5478969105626));
#497=CARTESIAN_POINT('',(0.657441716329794,15.421761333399,16.4244134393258));
#498=CARTESIAN_POINT('',(0.442287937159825,15.7508263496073,17.6602195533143));
#499=CARTESIAN_POINT('',(0.839097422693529,15.7395056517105,17.4686925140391));
#500=CARTESIAN_POINT('',(1.09982660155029,15.4066086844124,17.3439917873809));
#501=CARTESIAN_POINT('',(1.38326814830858,15.6962298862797,19.4929142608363));
#502=CARTESIAN_POINT('',(1.76178750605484,15.6626104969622,19.3036182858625));
#503=CARTESIAN_POINT('',(2.00007345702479,15.3350094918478,19.1766864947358));
#504=CARTESIAN_POINT('',(1.86207850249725,15.6472586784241,20.4060161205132));
#505=CARTESIAN_POINT('',(2.23085295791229,15.6031775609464,20.2178955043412));
#506=CARTESIAN_POINT('',(2.45796169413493,15.2784891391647,20.0897883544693));
#507=CARTESIAN_POINT('',(2.59100962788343,15.5373594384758,21.7682555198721));
#508=CARTESIAN_POINT('',(2.94538052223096,15.4781982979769,21.5836992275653));
#509=CARTESIAN_POINT('',(3.15476073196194,15.1588826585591,21.4520277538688));
#510=CARTESIAN_POINT('',(2.83583295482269,15.4946379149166,22.221208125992));
#511=CARTESIAN_POINT('',(3.18491939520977,15.4306905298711,22.0371892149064));
#512=CARTESIAN_POINT('',(3.3887458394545,15.1131942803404,21.9049803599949));
#513=CARTESIAN_POINT('',(3.32879853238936,15.3962558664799,23.1243318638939));
#514=CARTESIAN_POINT('',(3.66704854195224,15.3230536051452,22.9413523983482));
#515=CARTESIAN_POINT('',(3.85979797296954,15.0094522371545,22.8081040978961));
#516=CARTESIAN_POINT('',(3.57694105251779,15.3405942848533,23.5745027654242));
#517=CARTESIAN_POINT('',(3.90963807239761,15.262957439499,23.3920476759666));
#518=CARTESIAN_POINT('',(4.09686524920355,14.9513975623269,23.2582749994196));
#519=CARTESIAN_POINT('',(3.82661451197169,15.2780732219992,24.0231283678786));
#520=CARTESIAN_POINT('',(4.15397181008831,15.19608184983,23.8418093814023));
#521=CARTESIAN_POINT('',(4.33535141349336,14.8867874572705,23.7069006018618));
#522=(BOUNDED_SURFACE() B_SPLINE_SURFACE(3,2,((#396,#397,#398),(#399,#400,#401),(#402,#403,
#404),(#405,#406,#407),(#408,#409,#410),(#411,#412,#413),(#414,#415,#416),(#417,#418,#419),
(#420,#421,#422),(#423,#424,#425),(#426,#427,#428),(#429,#430,#431),(#432,#433,#434),(#435,#436,
#437),(#438,#439,#440),(#441,#442,#443),(#444,#445,#446),(#447,#448,#449),(#450,#451,#452),
(#453,#454,#455),(#456,#457,#458),(#459,#460,#461),(#462,#463,#464),(#465,#466,#467),(#468,#469,
#470),(#471,#472,#473),(#474,#475,#476),(#477,#478,#479),(#480,#481,#482),(#483,#484,#485),
(#486,#487,#488),(#489,#490,#491),(#492,#493,#494),(#495,#496,#497),(#498,#499,#500),(#501,#502,
#503),(#504,#505,#506),(#507,#508,#509),(#510,#511,#512),(#513,#514,#515),(#516,#517,#518),
(#519,#520,#521)),.UNSPECIFIED.,.F.,.F.,.F.) B_SPLINE_SURFACE_WITH_KNOTS((4,2,2,2,2,2,2,2,2,2,2,
2,2,2,2,2,2,2,2,2,4),(3,3),(0.,2.15746623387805,4.31494689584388,8.63044860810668,
12.9390085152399,17.2470756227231,19.2268658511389,21.2072723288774,25.352675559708,
29.498174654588,33.6423071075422,37.7873618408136,40.8203001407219,43.853282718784,
46.8851571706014,49.9169370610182,52.9656024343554,56.0138922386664,59.0676341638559,
60.5952423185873,62.1229752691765),(0.,1.),
.UNSPECIFIED.) GEOMETRIC_REPRESENTATION_ITEM() RATIONAL_B_SPLINE_SURFACE(((1.,0.734067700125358,
1.),(1.,0.737601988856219,1.),(1.,0.740959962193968,1.),(1.,0.747412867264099,1.),(1.,
0.750507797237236,1.),(1.,0.759533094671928,1.),(1.,0.765203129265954,1.),(1.,0.776135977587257,
1.),(1.,0.781399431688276,1.),(1.,0.791657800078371,1.),(1.,0.796652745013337,1.),(1.,
0.803798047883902,1.),(1.,0.806026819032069,1.),(1.,0.810447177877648,1.),(1.,0.812638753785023,
1.),(1.,0.81936518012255,1.),(1.,0.823842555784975,1.),(1.,0.832671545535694,1.),(1.,
0.83702315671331,1.),(1.,0.845614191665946,1.),(1.,0.849853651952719,1.),(1.,0.858232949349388,
1.),(1.,0.862372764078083,1.),(1.,0.869459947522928,1.),(1.,0.872429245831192,1.),(1.,
0.878319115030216,1.),(1.,0.881239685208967,1.),(1.,0.887031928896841,1.),(1.,0.889903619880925,
1.),(1.,0.895599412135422,1.),(1.,0.898423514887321,1.),(1.,0.904039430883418,1.),(1.,
0.906830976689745,1.),(1.,0.912364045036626,1.),(1.,0.915105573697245,1.),(1.,0.920541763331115,
1.),(1.,0.923236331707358,1.),(1.,0.927236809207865,1.),(1.,0.928563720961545,1.),(1.,
0.931203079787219,1.),(1.,0.932515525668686,1.),(1.,0.933820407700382,1.))) REPRESENTATION_ITEM('') SURFACE());
#523=CARTESIAN_POINT('',(3.82661451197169,15.2780732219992,24.0231283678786));
#524=CARTESIAN_POINT('',(3.57694105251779,15.3405942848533,23.5745027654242));
#525=CARTESIAN_POINT('',(3.32879853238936,15.3962558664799,23.1243318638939));
#526=CARTESIAN_POINT('',(2.83583295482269,15.4946379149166,22.221208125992));
#527=CARTESIAN_POINT('',(2.59100962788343,15.5373594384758,21.7682555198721));
#528=CARTESIAN_POINT('',(1.86207850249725,15.6472586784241,20.4060161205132));
#529=CARTESIAN_POINT('',(1.38326814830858,15.6962298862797,19.4929142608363));
#530=CARTESIAN_POINT('',(0.442287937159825,15.7508263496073,17.6602195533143));
#531=CARTESIAN_POINT('',(-0.0199101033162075,15.7565288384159,16.7406412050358));
#532=CARTESIAN_POINT('',(-0.927460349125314,15.7292217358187,14.8946185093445));
#533=CARTESIAN_POINT('',(-1.37281047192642,15.6962073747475,13.9681733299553));
#534=CARTESIAN_POINT('',(-2.24324773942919,15.5955507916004,12.1147826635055));
#535=CARTESIAN_POINT('',(-2.66843345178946,15.52810137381,11.1878683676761));
#536=CARTESIAN_POINT('',(-3.50044174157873,15.3619452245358,9.32927367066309));
#537=CARTESIAN_POINT('',(-3.90726374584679,15.2632375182,8.39759312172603));
#538=CARTESIAN_POINT('',(-4.70208528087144,15.0374078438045,6.52983951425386));
#539=CARTESIAN_POINT('',(-5.09007787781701,14.9102755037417,5.59376497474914));
#540=CARTESIAN_POINT('',(-5.84658779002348,14.6301940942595,3.71815198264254));
#541=CARTESIAN_POINT('',(-6.21510538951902,14.4772454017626,2.77861358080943));
#542=CARTESIAN_POINT('',(-7.06377311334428,14.0874592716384,0.551412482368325));
#543=CARTESIAN_POINT('',(-7.53530797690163,13.8404260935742,-0.737575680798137));
#544=CARTESIAN_POINT('',(-8.44032211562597,13.3078564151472,-3.3198931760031));
#545=CARTESIAN_POINT('',(-8.87380983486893,13.0223284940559,-4.61322147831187));
#546=CARTESIAN_POINT('',(-9.7023406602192,12.4173380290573,-7.20416657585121));
#547=CARTESIAN_POINT('',(-10.0973710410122,12.0978643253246,-8.5017846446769));
#548=CARTESIAN_POINT('',(-10.848298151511,11.4293314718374,-11.1002321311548));
#549=CARTESIAN_POINT('',(-11.2041957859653,11.0802730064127,-12.4010614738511));
#550=CARTESIAN_POINT('',(-11.7008806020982,10.545499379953,-14.3252513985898));
#551=CARTESIAN_POINT('',(-11.85693763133,10.3696850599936,-14.9476154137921));
#552=CARTESIAN_POINT('',(-12.1599418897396,10.0126479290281,-16.19270979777));
#553=CARTESIAN_POINT('',(-12.3068919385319,9.83142681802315,-16.8154399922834));
#554=CARTESIAN_POINT('',(-12.7591745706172,9.24780449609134,-18.7940891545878));
#555=CARTESIAN_POINT('',(-13.047532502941,8.83592444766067,-20.1510011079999));
#556=CARTESIAN_POINT('',(-13.5808987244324,7.99192896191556,-22.8668970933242));
#557=CARTESIAN_POINT('',(-13.8259020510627,7.55981121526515,-24.225881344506));
#558=CARTESIAN_POINT('',(-14.2726480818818,6.67821817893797,-26.9476140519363));
#559=CARTESIAN_POINT('',(-14.4743204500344,6.2287160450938,-28.3103650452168));
#560=CARTESIAN_POINT('',(-14.7438447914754,5.54451277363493,-30.3552125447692));
#561=CARTESIAN_POINT('',(-14.8281846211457,5.31480136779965,-31.0369058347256));
#562=CARTESIAN_POINT('',(-14.9858608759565,4.8524347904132,-32.4005280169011));
#563=CARTESIAN_POINT('',(-15.0591973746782,4.61977963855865,-33.0824569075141));
#564=CARTESIAN_POINT('',(-15.1270251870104,4.38584187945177,-33.7644915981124));
#565=B_SPLINE_CURVE_WITH_KNOTS('',3,(#523,#524,#525,#526,#527,#528,#529,#530,#531,#532,#533,
#534,#535,#536,#537,#538,#539,#540,#541,#542,#543,#544,#545,#546,#547,#548,#549,#550,#551,#552,
#553,#554,#555,#556,#557,#558,#559,#560,#561,#562,#563,#564),.UNSPECIFIED.,.F.,.F.,(4,2,2,2,2,2,
2,2,2,2,2,2,2,2,2,2,2,2,2,2,4),(0.,1.52773295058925,3.0553411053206,6.10908303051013,
9.15737283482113,12.2060382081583,15.2378180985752,18.2696925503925,21.3026751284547,
24.3356134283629,28.4806681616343,32.6248006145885,36.7702997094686,40.9157029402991,
42.8961094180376,44.8758996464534,49.1839667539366,53.4925266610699,57.8080283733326,
59.9655090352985,62.1229752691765),.UNSPECIFIED.);
#566=EDGE_CURVE('E213',#393,#350,#565,.T.);
#567=ORIENTED_EDGE('',*,*,#566,.T.);
#568=EDGE_LOOP('',(#352,#360,#369,#378,#386,#395,#567));
#569=FACE_BOUND('',#568,.T.);
#570=ADVANCED_FACE('F173',(#569),#341,.T.);
#571=CARTESIAN_POINT('',(-12.1259705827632,-3.93996667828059,-28.));
#572=VERTEX_POINT('',#571);
#573=CARTESIAN_POINT('',(-12.2818902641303,-3.42310846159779,-28.));
#574=VERTEX_POINT('',#573);
#575=EDGE_CURVE('E397',#572,#574,#47,.F.);
#576=ORIENTED_EDGE('',*,*,#575,.T.);
#577=DIRECTION('',(0.,0.,-1.));
#578=VECTOR('',#577,1.);
#579=CARTESIAN_POINT('',(-12.2818902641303,-3.42310846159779,4.));
#580=LINE('',#579,#578);
#581=CARTESIAN_POINT('',(-12.2818902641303,-3.42310846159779,-17.7038493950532));
#582=VERTEX_POINT('',#581);
#583=EDGE_CURVE('E386',#574,#582,#580,.F.);
#584=ORIENTED_EDGE('',*,*,#583,.T.);
#585=CARTESIAN_POINT('',(-12.1259705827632,-3.93996667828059,-18.5990740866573));
#586=VERTEX_POINT('',#585);
#587=EDGE_CURVE('E409',#582,#586,#28,.F.);
#588=ORIENTED_EDGE('',*,*,#587,.T.);
#589=DIRECTION('',(0.,0.,-1.));
#590=VECTOR('',#589,1.);
#591=CARTESIAN_POINT('',(-12.1259705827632,-3.93996667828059,4.));
#592=LINE('',#591,#590);
#593=EDGE_CURVE('E205',#586,#572,#592,.T.);
#594=ORIENTED_EDGE('',*,*,#593,.T.);
#595=EDGE_LOOP('',(#576,#584,#588,#594));
#596=FACE_BOUND('',#595,.T.);
#597=ADVANCED_FACE('F240',(#596),#23,.F.);
#598=CARTESIAN_POINT('',(-13.5525553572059,-4.40349216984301,4.));
#599=DIRECTION('',(0.,0.,-1.));
#600=DIRECTION('',(-1.,0.,0.));
#601=AXIS2_PLACEMENT_3D('',#598,#599,#600);
#602=CYLINDRICAL_SURFACE('',#601,1.5);
#603=ORIENTED_EDGE('',*,*,#593,.F.);
#604=CARTESIAN_POINT('',(-13.5525553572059,-4.40349216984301,-19.4019237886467));
#605=DIRECTION('',(0.,0.866025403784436,-0.500000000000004));
#606=DIRECTION('',(0.,-0.500000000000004,-0.866025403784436));
#607=AXIS2_PLACEMENT_3D('',#604,#605,#606);
#608=ELLIPSE('',#607,2.99999999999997,1.5);
#609=CARTESIAN_POINT('',(-14.9513838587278,-4.94504440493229,-20.3399197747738));
#610=VERTEX_POINT('',#609);
#611=EDGE_CURVE('E412',#610,#586,#608,.F.);
#612=ORIENTED_EDGE('',*,*,#611,.F.);
#613=DIRECTION('',(0.,0.,-1.));
#614=VECTOR('',#613,1.);
#615=CARTESIAN_POINT('',(-14.9513838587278,-4.94504440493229,4.));
#616=LINE('',#615,#614);
#617=CARTESIAN_POINT('',(-14.9513838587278,-4.94504440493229,-28.));
#618=VERTEX_POINT('',#617);
#619=EDGE_CURVE('E432',#610,#618,#616,.T.);
#620=ORIENTED_EDGE('',*,*,#619,.T.);
#621=CARTESIAN_POINT('',(-13.5525553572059,-4.40349216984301,-28.));
#622=DIRECTION('',(0.,0.,1.));
#623=DIRECTION('',(1.,0.,0.));
#624=AXIS2_PLACEMENT_3D('',#621,#622,#623);
#625=CIRCLE('',#624,1.5);
#626=EDGE_CURVE('E193',#572,#618,#625,.F.);
#627=ORIENTED_EDGE('',*,*,#626,.F.);
#628=EDGE_LOOP('',(#603,#612,#620,#627));
#629=FACE_BOUND('',#628,.T.);
#630=ADVANCED_FACE('F241',(#629),#602,.T.);
#631=CARTESIAN_POINT('',(6.46936462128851,12.6968429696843,4.));
#632=DIRECTION('',(0.,0.,-1.));
#633=DIRECTION('',(-1.,0.,0.));
#634=AXIS2_PLACEMENT_3D('',#631,#632,#633);
#635=CYLINDRICAL_SURFACE('',#634,1.5);
#636=CARTESIAN_POINT('',(6.46936462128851,12.6968429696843,0.));
#637=DIRECTION('',(0.,0.,1.));
#638=DIRECTION('',(1.,0.,0.));
#639=AXIS2_PLACEMENT_3D('',#636,#637,#638);
#640=CIRCLE('',#639,1.5);
#641=EDGE_CURVE('E186',#384,#316,#640,.F.);
#642=ORIENTED_EDGE('',*,*,#641,.F.);
#643=ORIENTED_EDGE('',*,*,#385,.F.);
#644=CARTESIAN_POINT('',(6.46936462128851,12.6968429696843,4.));
#645=DIRECTION('',(0.,0.,1.));
#646=DIRECTION('',(1.,0.,0.));
#647=AXIS2_PLACEMENT_3D('',#644,#645,#646);
#648=CIRCLE('',#647,1.5);
#649=EDGE_CURVE('E184',#376,#324,#648,.F.);
#650=ORIENTED_EDGE('',*,*,#649,.T.);
#651=ORIENTED_EDGE('',*,*,#325,.T.);
#652=EDGE_LOOP('',(#642,#643,#650,#651));
#653=FACE_BOUND('',#652,.T.);
#654=ADVANCED_FACE('F295',(#653),#635,.T.);
#655=CARTESIAN_POINT('',(0.,0.,4.));
#656=DIRECTION('',(0.,0.,1.));
#657=DIRECTION('',(1.,0.,0.));
#658=AXIS2_PLACEMENT_3D('',#655,#656,#657);
#659=PLANE('',#658);
#660=DIRECTION('',(1.,0.,0.));
#661=VECTOR('',#660,1.);
#662=CARTESIAN_POINT('',(-17.,9.10761482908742,4.));
#663=LINE('',#662,#661);
#664=EDGE_CURVE('E158',#367,#30,#663,.T.);
#665=ORIENTED_EDGE('',*,*,#664,.T.);
#666=ORIENTED_EDGE('',*,*,#332,.T.);
#667=ORIENTED_EDGE('',*,*,#649,.F.);
#668=ORIENTED_EDGE('',*,*,#377,.F.);
#669=EDGE_LOOP('',(#665,#666,#667,#668));
#670=FACE_BOUND('',#669,.T.);
#671=ADVANCED_FACE('F182',(#670),#659,.T.);
#672=CARTESIAN_POINT('',(0.,0.,0.));
#673=DIRECTION('',(0.,0.,1.));
#674=DIRECTION('',(1.,0.,0.));
#675=AXIS2_PLACEMENT_3D('',#672,#673,#674);
#676=PLANE('',#675);
#677=ORIENTED_EDGE('',*,*,#317,.F.);
#678=CARTESIAN_POINT('',(-5.42412642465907,11.538689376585,0.));
#679=CARTESIAN_POINT('',(-5.36671574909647,11.5656417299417,0.));
#680=CARTESIAN_POINT('',(-5.31156281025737,11.5974232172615,0.));
#681=CARTESIAN_POINT('',(-5.20720929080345,11.6697410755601,0.));
#682=CARTESIAN_POINT('',(-5.15801787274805,11.7102906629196,0.));
#683=CARTESIAN_POINT('',(-5.06715504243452,11.7992053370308,0.));
#684=CARTESIAN_POINT('',(-5.02549243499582,11.8475794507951,0.));
#685=CARTESIAN_POINT('',(-4.95125737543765,11.9508266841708,0.));
#686=CARTESIAN_POINT('',(-4.91867740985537,12.005694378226,0.));
#687=CARTESIAN_POINT('',(-4.86491957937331,12.1183673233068,0.));
#688=CARTESIAN_POINT('',(-4.84337573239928,12.1759974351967,0.));
#689=CARTESIAN_POINT('',(-4.81103712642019,12.2942244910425,0.));
#690=CARTESIAN_POINT('',(-4.80024107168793,12.3548210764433,0.));
#691=CARTESIAN_POINT('',(-4.79048906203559,12.4728672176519,0.));
#692=CARTESIAN_POINT('',(-4.79078748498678,12.5302552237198,0.));
#693=CARTESIAN_POINT('',(-4.80164692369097,12.6440326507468,0.));
#694=CARTESIAN_POINT('',(-4.81220049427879,12.7004227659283,0.));
#695=CARTESIAN_POINT('',(-4.84246350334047,12.8071284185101,0.));
#696=CARTESIAN_POINT('',(-4.86160267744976,12.8576064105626,0.));
#697=CARTESIAN_POINT('',(-4.90828387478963,12.9545417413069,0.));
#698=CARTESIAN_POINT('',(-4.93582816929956,13.0009979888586,0.));
#699=CARTESIAN_POINT('',(-4.99608886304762,13.0852158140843,0.));
#700=CARTESIAN_POINT('',(-5.02826260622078,13.1233681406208,0.));
#701=CARTESIAN_POINT('',(-5.09811867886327,13.1942190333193,0.));
#702=CARTESIAN_POINT('',(-5.13579899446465,13.2269195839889,0.));
#703=CARTESIAN_POINT('',(-5.1757821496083,13.256498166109,0.));
#704=B_SPLINE_CURVE_WITH_KNOTS('',3,(#678,#679,#680,#681,#682,#683,#684,#685,#686,#687,#688,
#689,#690,#691,#692,#693,#694,#695,#696,#697,#698,#699,#700,#701,#702,#703),.UNSPECIFIED.,.F.,
.F.,(4,2,2,2,2,2,2,2,2,2,2,2,4),(0.,0.190067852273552,0.380424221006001,0.571001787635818,
0.761421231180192,0.94503325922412,1.12862314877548,1.29989840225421,1.47104940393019,
1.632212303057,1.79341879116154,1.94253805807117,2.09160292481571),.UNSPECIFIED.);
#705=CARTESIAN_POINT('',(-5.17578214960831,13.256498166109,0.));
#706=VERTEX_POINT('',#705);
#707=EDGE_CURVE('E268',#307,#706,#704,.T.);
#708=ORIENTED_EDGE('',*,*,#707,.T.);
#709=CARTESIAN_POINT('',(-15.,0.,0.));
#710=DIRECTION('',(0.,0.,1.));
#711=DIRECTION('',(1.,0.,0.));
#712=AXIS2_PLACEMENT_3D('',#709,#710,#711);
#713=CIRCLE('',#712,16.5000000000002);
#714=CARTESIAN_POINT('',(-6.18373538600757,13.9471673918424,0.));
#715=VERTEX_POINT('',#714);
#716=EDGE_CURVE('E207',#706,#715,#713,.T.);
#717=ORIENTED_EDGE('',*,*,#716,.T.);
#718=CARTESIAN_POINT('',(-6.18373538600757,13.9471673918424,0.));
#719=CARTESIAN_POINT('',(-6.20833263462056,13.9627194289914,0.));
#720=CARTESIAN_POINT('',(-6.23360762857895,13.9771669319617,0.));
#721=CARTESIAN_POINT('',(-6.28531159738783,14.0037957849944,0.));
#722=CARTESIAN_POINT('',(-6.31174008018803,14.0159780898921,0.));
#723=CARTESIAN_POINT('',(-6.39225253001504,14.0489643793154,0.));
#724=CARTESIAN_POINT('',(-6.44778001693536,14.0663433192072,0.));
#725=CARTESIAN_POINT('',(-6.56081586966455,14.0917074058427,0.));
#726=CARTESIAN_POINT('',(-6.61832160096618,14.0997045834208,0.));
#727=CARTESIAN_POINT('',(-6.73393766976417,14.1064428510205,0.));
#728=CARTESIAN_POINT('',(-6.79204867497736,14.1051723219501,0.));
#729=CARTESIAN_POINT('',(-6.91032887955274,14.0933452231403,0.));
#730=CARTESIAN_POINT('',(-6.97045011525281,14.0823141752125,0.));
#731=CARTESIAN_POINT('',(-7.08806013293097,14.0507845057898,0.));
#732=CARTESIAN_POINT('',(-7.14555346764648,14.0303029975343,0.));
#733=CARTESIAN_POINT('',(-7.22113637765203,13.9964169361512,0.));
#734=CARTESIAN_POINT('',(-7.24098714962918,13.9868207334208,0.));
#735=CARTESIAN_POINT('',(-7.26053441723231,13.9766641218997,0.));
#736=B_SPLINE_CURVE_WITH_KNOTS('',3,(#718,#719,#720,#721,#722,#723,#724,#725,#726,#727,#728,
#729,#730,#731,#732,#733,#734,#735),.UNSPECIFIED.,.F.,.F.,(4,2,2,2,2,2,2,2,4),(0.,
0.0872429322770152,0.174449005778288,0.348105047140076,0.521538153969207,0.695188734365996,
0.87777505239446,1.0600320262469,1.12613756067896),.UNSPECIFIED.);
#737=EDGE_CURVE('E305',#715,#393,#736,.T.);
#738=ORIENTED_EDGE('',*,*,#737,.T.);
#739=ORIENTED_EDGE('',*,*,#394,.T.);
#740=ORIENTED_EDGE('',*,*,#641,.T.);
#741=EDGE_LOOP('',(#677,#708,#717,#738,#739,#740));
#742=FACE_BOUND('',#741,.T.);
#743=ADVANCED_FACE('F317',(#742),#676,.F.);
#744=CARTESIAN_POINT('',(0.,0.,-28.));
#745=DIRECTION('',(0.,0.,1.));
#746=DIRECTION('',(1.,0.,0.));
#747=AXIS2_PLACEMENT_3D('',#744,#745,#746);
#748=PLANE('',#747);
#749=CARTESIAN_POINT('',(-13.7477270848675,3.75,-28.));
#750=DIRECTION('',(0.,0.,-1.));
#751=DIRECTION('',(-1.,0.,0.));
#752=AXIS2_PLACEMENT_3D('',#749,#750,#751);
#753=CIRCLE('',#752,0.999999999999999);
#754=CARTESIAN_POINT('',(-14.7477270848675,3.75,-28.));
#755=VERTEX_POINT('',#754);
#756=EDGE_CURVE('E179',#755,#755,#753,.T.);
#757=ORIENTED_EDGE('',*,*,#756,.F.);
#758=EDGE_LOOP('',(#757));
#759=FACE_BOUND('',#758,.T.);
#760=CARTESIAN_POINT('',(-13.7477270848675,-3.75,-28.));
#761=DIRECTION('',(0.,0.,-1.));
#762=DIRECTION('',(-1.,0.,0.));
#763=AXIS2_PLACEMENT_3D('',#760,#761,#762);
#764=CIRCLE('',#763,0.999999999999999);
#765=CARTESIAN_POINT('',(-14.7477270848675,-3.75,-28.));
#766=VERTEX_POINT('',#765);
#767=EDGE_CURVE('E420',#766,#766,#764,.T.);
#768=ORIENTED_EDGE('',*,*,#767,.F.);
#769=EDGE_LOOP('',(#768));
#770=FACE_BOUND('',#769,.T.);
#771=CARTESIAN_POINT('',(-15.,0.,-28.));
#772=DIRECTION('',(0.,0.,1.));
#773=DIRECTION('',(1.,0.,0.));
#774=AXIS2_PLACEMENT_3D('',#771,#772,#773);
#775=CIRCLE('',#774,1.25);
#776=CARTESIAN_POINT('',(-13.75,0.,-28.));
#777=VERTEX_POINT('',#776);
#778=EDGE_CURVE('E426',#777,#777,#775,.T.);
#779=ORIENTED_EDGE('',*,*,#778,.T.);
#780=EDGE_LOOP('',(#779));
#781=FACE_BOUND('',#780,.T.);
#782=ORIENTED_EDGE('',*,*,#626,.T.);
#783=CARTESIAN_POINT('',(-12.8904871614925,-2.76497449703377,-28.));
#784=DIRECTION('',(0.,0.,1.));
#785=DIRECTION('',(1.,0.,0.));
#786=AXIS2_PLACEMENT_3D('',#783,#784,#785);
#787=CIRCLE('',#786,3.);
#788=CARTESIAN_POINT('',(-15.0583525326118,-4.83870536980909,-28.));
#789=VERTEX_POINT('',#788);
#790=EDGE_CURVE('E365',#618,#789,#787,.F.);
#791=ORIENTED_EDGE('',*,*,#790,.T.);
#792=CARTESIAN_POINT('',(-10.,0.,-28.));
#793=DIRECTION('',(0.,0.,1.));
#794=DIRECTION('',(1.,0.,0.));
#795=AXIS2_PLACEMENT_3D('',#792,#793,#794);
#796=CIRCLE('',#795,7.);
#797=CARTESIAN_POINT('',(-15.3046875,4.567306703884,-28.));
#798=VERTEX_POINT('',#797);
#799=EDGE_CURVE('E429',#798,#789,#796,.T.);
#800=ORIENTED_EDGE('',*,*,#799,.F.);
#801=CARTESIAN_POINT('',(-17.578125,6.52472386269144,-28.));
#802=DIRECTION('',(0.,0.,1.));
#803=DIRECTION('',(1.,0.,0.));
#804=AXIS2_PLACEMENT_3D('',#801,#802,#803);
#805=CIRCLE('',#804,3.);
#806=EDGE_CURVE('E388',#798,#348,#805,.T.);
#807=ORIENTED_EDGE('',*,*,#806,.T.);
#808=ORIENTED_EDGE('',*,*,#351,.T.);
#809=CARTESIAN_POINT('',(-14.422335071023,6.32919829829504,-28.));
#810=CARTESIAN_POINT('',(-14.3975199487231,6.38583652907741,-28.));
#811=CARTESIAN_POINT('',(-14.3679200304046,6.44037979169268,-28.));
#812=CARTESIAN_POINT('',(-14.3000369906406,6.54386084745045,-28.));
#813=CARTESIAN_POINT('',(-14.2617431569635,6.59279161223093,-28.));
#814=CARTESIAN_POINT('',(-14.17738647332,6.68352562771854,-28.));
#815=CARTESIAN_POINT('',(-14.1313166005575,6.72532236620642,-28.));
#816=CARTESIAN_POINT('',(-14.0326767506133,6.80031133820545,-28.));
#817=CARTESIAN_POINT('',(-13.9801118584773,6.83351024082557,-28.));
#818=CARTESIAN_POINT('',(-13.8713834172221,6.88932470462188,-28.));
#819=CARTESIAN_POINT('',(-13.8153525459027,6.91219796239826,-28.));
#820=CARTESIAN_POINT('',(-13.7001259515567,6.94763753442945,-28.));
#821=CARTESIAN_POINT('',(-13.6409311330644,6.96020677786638,-28.));
#822=CARTESIAN_POINT('',(-13.5223901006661,6.97419871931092,-28.));
#823=CARTESIAN_POINT('',(-13.4630705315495,6.97583906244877,-28.));
#824=CARTESIAN_POINT('',(-13.3745924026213,6.97016454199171,-28.));
#825=CARTESIAN_POINT('',(-13.3451274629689,6.96690314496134,-28.));
#826=CARTESIAN_POINT('',(-13.2866167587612,6.95766512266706,-28.));
#827=CARTESIAN_POINT('',(-13.257571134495,6.9516876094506,-28.));
#828=CARTESIAN_POINT('',(-13.2288513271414,6.94436055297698,-28.));
#829=B_SPLINE_CURVE_WITH_KNOTS('',3,(#809,#810,#811,#812,#813,#814,#815,#816,#817,#818,#819,
#820,#821,#822,#823,#824,#825,#826,#827,#828),.UNSPECIFIED.,.F.,.F.,(4,2,2,2,2,2,2,2,2,4),(0.,
0.18530061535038,0.370830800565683,0.556529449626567,0.742083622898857,0.922709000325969,
1.10328301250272,1.28024992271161,1.36907316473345,1.45792546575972),.UNSPECIFIED.);
#830=CARTESIAN_POINT('',(-13.2288513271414,6.94436055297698,-28.));
#831=VERTEX_POINT('',#830);
#832=EDGE_CURVE('E333',#350,#831,#829,.T.);
#833=ORIENTED_EDGE('',*,*,#832,.T.);
#834=CARTESIAN_POINT('',(-15.,0.,-28.));
#835=DIRECTION('',(0.,0.,1.));
#836=DIRECTION('',(1.,0.,0.));
#837=AXIS2_PLACEMENT_3D('',#834,#835,#836);
#838=CIRCLE('',#837,7.1666666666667);
#839=CARTESIAN_POINT('',(-12.1339089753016,6.56860969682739,-28.));
#840=VERTEX_POINT('',#839);
#841=EDGE_CURVE('E210',#831,#840,#838,.F.);
#842=ORIENTED_EDGE('',*,*,#841,.T.);
#843=CARTESIAN_POINT('',(-12.1339089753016,6.56860969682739,-28.));
#844=CARTESIAN_POINT('',(-12.1091055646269,6.55778794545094,-28.));
#845=CARTESIAN_POINT('',(-12.0847781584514,6.54590844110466,-28.));
#846=CARTESIAN_POINT('',(-12.0372284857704,6.52011991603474,-28.));
#847=CARTESIAN_POINT('',(-12.0140060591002,6.50621119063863,-28.));
#848=CARTESIAN_POINT('',(-11.9463513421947,6.46165456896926,-28.));
#849=CARTESIAN_POINT('',(-11.9037804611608,6.42811000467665,-28.));
#850=CARTESIAN_POINT('',(-11.8248832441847,6.35438950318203,-28.));
#851=CARTESIAN_POINT('',(-11.7885569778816,6.31421349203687,-28.));
#852=CARTESIAN_POINT('',(-11.7229930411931,6.22843450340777,-28.));
#853=CARTESIAN_POINT('',(-11.6937569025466,6.1828303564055,-28.));
#854=CARTESIAN_POINT('',(-11.6424632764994,6.0865326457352,-28.));
#855=CARTESIAN_POINT('',(-11.6205682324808,6.03575277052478,-28.));
#856=CARTESIAN_POINT('',(-11.5851721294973,5.93134913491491,-28.));
#857=CARTESIAN_POINT('',(-11.5716730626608,5.87772470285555,-28.));
#858=CARTESIAN_POINT('',(-11.5527503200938,5.76638790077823,-28.));
#859=CARTESIAN_POINT('',(-11.5477512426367,5.70860354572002,-28.));
#860=CARTESIAN_POINT('',(-11.5470489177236,5.59297259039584,-28.));
#861=CARTESIAN_POINT('',(-11.5513474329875,5.5351259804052,-28.));
#862=CARTESIAN_POINT('',(-11.5676693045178,5.42929800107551,-28.));
#863=CARTESIAN_POINT('',(-11.5784580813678,5.38112135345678,-28.));
#864=CARTESIAN_POINT('',(-11.6063089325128,5.28668764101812,-28.));
#865=CARTESIAN_POINT('',(-11.6233624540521,5.24042805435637,-28.));
#866=CARTESIAN_POINT('',(-11.6434217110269,5.19550102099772,-28.));
#867=B_SPLINE_CURVE_WITH_KNOTS('',3,(#843,#844,#845,#846,#847,#848,#849,#850,#851,#852,#853,
#854,#855,#856,#857,#858,#859,#860,#861,#862,#863,#864,#865,#866),.UNSPECIFIED.,.F.,.F.,(4,2,2,
2,2,2,2,2,2,2,2,4),(0.,0.0811331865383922,0.162254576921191,0.324008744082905,0.48576471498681,
0.647555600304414,0.812720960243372,0.977925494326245,1.15116336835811,1.32443408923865,
1.47211567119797,1.61959638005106),.UNSPECIFIED.);
#868=EDGE_CURVE('E225',#840,#49,#867,.T.);
#869=ORIENTED_EDGE('',*,*,#868,.T.);
#870=ORIENTED_EDGE('',*,*,#50,.F.);
#871=CARTESIAN_POINT('',(-9.39203373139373,2.61767117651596,-28.));
#872=DIRECTION('',(0.,0.,1.));
#873=DIRECTION('',(1.,0.,0.));
#874=AXIS2_PLACEMENT_3D('',#871,#872,#873);
#875=CIRCLE('',#874,3.);
#876=CARTESIAN_POINT('',(-12.3920337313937,2.61767117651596,-28.));
#877=VERTEX_POINT('',#876);
#878=EDGE_CURVE('E392',#40,#877,#875,.T.);
#879=ORIENTED_EDGE('',*,*,#878,.T.);
#880=DIRECTION('',(0.,1.,0.));
#881=VECTOR('',#880,1.);
#882=CARTESIAN_POINT('',(-12.3920337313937,0.,-28.));
#883=LINE('',#882,#881);
#884=CARTESIAN_POINT('',(-12.3920337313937,-2.61767117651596,-28.));
#885=VERTEX_POINT('',#884);
#886=EDGE_CURVE('E399',#885,#877,#883,.T.);
#887=ORIENTED_EDGE('',*,*,#886,.F.);
#888=CARTESIAN_POINT('',(-9.39203373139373,-2.61767117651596,-28.));
#889=DIRECTION('',(0.,0.,1.));
#890=DIRECTION('',(1.,0.,0.));
#891=AXIS2_PLACEMENT_3D('',#888,#889,#890);
#892=CIRCLE('',#891,3.);
#893=EDGE_CURVE('E49',#885,#574,#892,.T.);
#894=ORIENTED_EDGE('',*,*,#893,.T.);
#895=ORIENTED_EDGE('',*,*,#575,.F.);
#896=EDGE_LOOP('',(#782,#791,#800,#807,#808,#833,#842,#869,#870,#879,#887,#894,#895));
#897=FACE_BOUND('',#896,.T.);
#898=ADVANCED_FACE('F321',(#759,#770,#781,#897),#748,.F.);
#899=CARTESIAN_POINT('',(-12.3920337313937,0.,2.));
#900=DIRECTION('',(-1.,0.,0.));
#901=DIRECTION('',(0.,0.,1.));
#902=AXIS2_PLACEMENT_3D('',#899,#900,#901);
#903=PLANE('',#902);
#904=ORIENTED_EDGE('',*,*,#886,.T.);
#905=DIRECTION('',(0.,0.,1.));
#906=VECTOR('',#905,1.);
#907=CARTESIAN_POINT('',(-12.3920337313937,2.61767117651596,-6.5786991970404));
#908=LINE('',#907,#906);
#909=CARTESIAN_POINT('',(-12.3920337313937,2.61767117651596,-7.24091214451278));
#910=VERTEX_POINT('',#909);
#911=EDGE_CURVE('E384',#877,#910,#908,.T.);
#912=ORIENTED_EDGE('',*,*,#911,.T.);
#913=DIRECTION('',(0.,-0.500000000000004,-0.866025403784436));
#914=VECTOR('',#913,1.);
#915=CARTESIAN_POINT('',(-12.3920337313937,5.96468571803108,-1.4437129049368));
#916=LINE('',#915,#914);
#917=CARTESIAN_POINT('',(-12.3920337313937,-2.61767117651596,-16.3087910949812));
#918=VERTEX_POINT('',#917);
#919=EDGE_CURVE('E408',#910,#918,#916,.T.);
#920=ORIENTED_EDGE('',*,*,#919,.T.);
#921=DIRECTION('',(0.,0.,1.));
#922=VECTOR('',#921,1.);
#923=CARTESIAN_POINT('',(-12.3920337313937,-2.61767117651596,-28.));
#924=LINE('',#923,#922);
#925=EDGE_CURVE('E381',#918,#885,#924,.F.);
#926=ORIENTED_EDGE('',*,*,#925,.T.);
#927=EDGE_LOOP('',(#904,#912,#920,#926));
#928=FACE_BOUND('',#927,.T.);
#929=ADVANCED_FACE('F328',(#928),#903,.F.);
#930=CARTESIAN_POINT('',(-10.,0.,2.));
#931=DIRECTION('',(0.,0.,-1.));
#932=DIRECTION('',(-1.,0.,0.));
#933=AXIS2_PLACEMENT_3D('',#930,#931,#932);
#934=CYLINDRICAL_SURFACE('',#933,7.);
#935=ORIENTED_EDGE('',*,*,#799,.T.);
#936=DIRECTION('',(0.,0.,-1.));
#937=VECTOR('',#936,1.);
#938=CARTESIAN_POINT('',(-15.0583525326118,-4.83870536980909,2.));
#939=LINE('',#938,#937);
#940=CARTESIAN_POINT('',(-15.0583525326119,-4.83870536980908,-20.1557351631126));
#941=VERTEX_POINT('',#940);
#942=EDGE_CURVE('E372',#789,#941,#939,.F.);
#943=ORIENTED_EDGE('',*,*,#942,.T.);
#944=CARTESIAN_POINT('',(-10.,0.,-11.774851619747));
#945=DIRECTION('',(0.,0.866025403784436,-0.500000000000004));
#946=DIRECTION('',(0.,-0.500000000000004,-0.866025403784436));
#947=AXIS2_PLACEMENT_3D('',#944,#945,#946);
#948=ELLIPSE('',#947,13.9999999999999,7.);
#949=CARTESIAN_POINT('',(-15.3046875,4.567306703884,-3.86404435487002));
#950=VERTEX_POINT('',#949);
#951=EDGE_CURVE('E216',#941,#950,#948,.T.);
#952=ORIENTED_EDGE('',*,*,#951,.T.);
#953=DIRECTION('',(0.,0.,-1.));
#954=VECTOR('',#953,1.);
#955=CARTESIAN_POINT('',(-15.3046875,4.567306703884,2.));
#956=LINE('',#955,#954);
#957=EDGE_CURVE('E366',#950,#798,#956,.T.);
#958=ORIENTED_EDGE('',*,*,#957,.T.);
#959=EDGE_LOOP('',(#935,#943,#952,#958));
#960=FACE_BOUND('',#959,.T.);
#961=ADVANCED_FACE('F330',(#960),#934,.T.);
#962=CARTESIAN_POINT('',(-15.,0.,2.));
#963=DIRECTION('',(0.,0.,-1.));
#964=DIRECTION('',(-1.,0.,0.));
#965=AXIS2_PLACEMENT_3D('',#962,#963,#964);
#966=CYLINDRICAL_SURFACE('',#965,1.25);
#967=CARTESIAN_POINT('',(-15.,0.,-11.774851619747));
#968=DIRECTION('',(0.,0.866025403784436,-0.500000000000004));
#969=DIRECTION('',(0.,-0.500000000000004,-0.866025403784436));
#970=AXIS2_PLACEMENT_3D('',#967,#968,#969);
#971=ELLIPSE('',#970,2.49999999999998,1.25);
#972=CARTESIAN_POINT('',(-15.,-1.25,-13.939915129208));
#973=VERTEX_POINT('',#972);
#974=EDGE_CURVE('E169',#973,#973,#971,.T.);
#975=ORIENTED_EDGE('',*,*,#974,.F.);
#976=EDGE_LOOP('',(#975));
#977=FACE_BOUND('',#976,.T.);
#978=ORIENTED_EDGE('',*,*,#778,.F.);
#979=EDGE_LOOP('',(#978));
#980=FACE_BOUND('',#979,.T.);
#981=ADVANCED_FACE('F505',(#977,#980),#966,.F.);
#982=CARTESIAN_POINT('',(-13.7477270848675,-3.75,-21.));
#983=DIRECTION('',(0.,0.,-1.));
#984=DIRECTION('',(-1.,0.,0.));
#985=AXIS2_PLACEMENT_3D('',#982,#983,#984);
#986=CONICAL_SURFACE('',#985,0.999999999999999,1.02974425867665);
#987=CARTESIAN_POINT('',(-13.7477270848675,-3.75,-20.3991393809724));
#988=VERTEX_POINT('',#987);
#989=VERTEX_LOOP('',#988);
#990=FACE_BOUND('',#989,.T.);
#991=CARTESIAN_POINT('',(-13.7477270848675,-3.75,-21.));
#992=DIRECTION('',(0.,0.,-1.));
#993=DIRECTION('',(-1.,0.,0.));
#994=AXIS2_PLACEMENT_3D('',#991,#992,#993);
#995=CIRCLE('',#994,0.999999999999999);
#996=CARTESIAN_POINT('',(-14.7477270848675,-3.75,-21.));
#997=VERTEX_POINT('',#996);
#998=EDGE_CURVE('E423',#997,#997,#995,.T.);
#999=ORIENTED_EDGE('',*,*,#998,.T.);
#1000=EDGE_LOOP('',(#999));
#1001=FACE_BOUND('',#1000,.T.);
#1002=ADVANCED_FACE('F511',(#990,#1001),#986,.F.);
#1003=CARTESIAN_POINT('',(-13.7477270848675,-3.75,-28.));
#1004=DIRECTION('',(0.,0.,-1.));
#1005=DIRECTION('',(-1.,0.,0.));
#1006=AXIS2_PLACEMENT_3D('',#1003,#1004,#1005);
#1007=CYLINDRICAL_SURFACE('',#1006,0.999999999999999);
#1008=ORIENTED_EDGE('',*,*,#998,.F.);
#1009=EDGE_LOOP('',(#1008));
#1010=FACE_BOUND('',#1009,.T.);
#1011=ORIENTED_EDGE('',*,*,#767,.T.);
#1012=EDGE_LOOP('',(#1011));
#1013=FACE_BOUND('',#1012,.T.);
#1014=ADVANCED_FACE('F518',(#1010,#1013),#1007,.F.);
#1015=CARTESIAN_POINT('',(-13.7477270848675,3.75,-21.));
#1016=DIRECTION('',(0.,0.,-1.));
#1017=DIRECTION('',(-1.,0.,0.));
#1018=AXIS2_PLACEMENT_3D('',#1015,#1016,#1017);
#1019=CONICAL_SURFACE('',#1018,0.999999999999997,1.02974425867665);
#1020=CARTESIAN_POINT('',(-13.7477270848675,3.75,-20.3991393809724));
#1021=VERTEX_POINT('',#1020);
#1022=VERTEX_LOOP('',#1021);
#1023=FACE_BOUND('',#1022,.T.);
#1024=CARTESIAN_POINT('',(-13.7477270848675,3.75,-21.));
#1025=DIRECTION('',(0.,0.,-1.));
#1026=DIRECTION('',(-1.,0.,0.));
#1027=AXIS2_PLACEMENT_3D('',#1024,#1025,#1026);
#1028=CIRCLE('',#1027,0.999999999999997);
#1029=CARTESIAN_POINT('',(-14.7477270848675,3.75,-21.));
#1030=VERTEX_POINT('',#1029);
#1031=EDGE_CURVE('E417',#1030,#1030,#1028,.T.);
#1032=ORIENTED_EDGE('',*,*,#1031,.T.);
#1033=EDGE_LOOP('',(#1032));
#1034=FACE_BOUND('',#1033,.T.);
#1035=ADVANCED_FACE('F526',(#1023,#1034),#1019,.F.);
#1036=CARTESIAN_POINT('',(-13.7477270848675,3.75,-28.));
#1037=DIRECTION('',(0.,0.,-1.));
#1038=DIRECTION('',(-1.,0.,0.));
#1039=AXIS2_PLACEMENT_3D('',#1036,#1037,#1038);
#1040=CYLINDRICAL_SURFACE('',#1039,0.999999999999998);
#1041=ORIENTED_EDGE('',*,*,#1031,.F.);
#1042=EDGE_LOOP('',(#1041));
#1043=FACE_BOUND('',#1042,.T.);
#1044=ORIENTED_EDGE('',*,*,#756,.T.);
#1045=EDGE_LOOP('',(#1044));
#1046=FACE_BOUND('',#1045,.T.);
#1047=ADVANCED_FACE('F534',(#1043,#1046),#1040,.F.);
#1048=CARTESIAN_POINT('',(-15.,0.,0.));
#1049=DIRECTION('',(0.,0.,1.));
#1050=DIRECTION('',(1.,0.,0.));
#1051=AXIS2_PLACEMENT_3D('',#1048,#1049,#1050);
#1052=CONICAL_SURFACE('',#1051,16.5000000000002,0.321750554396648);
#1053=ORIENTED_EDGE('',*,*,#841,.F.);
#1054=CARTESIAN_POINT('',(-13.9779277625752,5.03711260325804,-34.0807193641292));
#1055=CARTESIAN_POINT('',(-13.9102353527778,5.25535257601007,-33.3986846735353));
#1056=CARTESIAN_POINT('',(-13.8369452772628,5.47226977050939,-32.7167557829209));
#1057=CARTESIAN_POINT('',(-13.6794196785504,5.90312590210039,-31.3531336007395));
#1058=CARTESIAN_POINT('',(-13.5951840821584,6.11706481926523,-30.6714403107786));
#1059=CARTESIAN_POINT('',(-13.3264128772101,6.75396391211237,-28.6265928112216));
#1060=CARTESIAN_POINT('',(-13.125829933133,7.17195159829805,-27.26384181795));
#1061=CARTESIAN_POINT('',(-12.6832114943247,7.99087232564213,-24.5421091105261));
#1062=CARTESIAN_POINT('',(-12.4412431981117,8.39183171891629,-23.1831248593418));
#1063=CARTESIAN_POINT('',(-11.9162215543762,9.17404272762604,-20.467228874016));
#1064=CARTESIAN_POINT('',(-11.6331729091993,9.55529659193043,-19.1103169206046));
#1065=CARTESIAN_POINT('',(-11.190420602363,10.09476886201,-17.1316677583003));
#1066=CARTESIAN_POINT('',(-11.0467289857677,10.262168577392,-16.5089375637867));
#1067=CARTESIAN_POINT('',(-10.7507667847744,10.5917394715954,-15.2638431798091));
#1068=CARTESIAN_POINT('',(-10.5984935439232,10.7539090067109,-14.6414791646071));
#1069=CARTESIAN_POINT('',(-10.114336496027,11.2467899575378,-12.7172892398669));
#1070=CARTESIAN_POINT('',(-9.76808334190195,11.5679432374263,-11.416459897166));
#1071=CARTESIAN_POINT('',(-9.03881728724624,12.181768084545,-8.81801241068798));
#1072=CARTESIAN_POINT('',(-8.6558035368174,12.4744389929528,-7.52039434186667));
#1073=CARTESIAN_POINT('',(-7.85368529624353,13.0271612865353,-4.92944924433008));
#1074=CARTESIAN_POINT('',(-7.43459274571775,13.2872233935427,-3.63612094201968));
#1075=CARTESIAN_POINT('',(-6.56074783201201,13.7704275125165,-1.05380344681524));
#1076=CARTESIAN_POINT('',(-6.10598755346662,13.9935612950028,0.23518471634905));
#1077=CARTESIAN_POINT('',(-5.28840379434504,14.3435560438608,2.46238581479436));
#1078=CARTESIAN_POINT('',(-4.93364947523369,14.4801847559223,3.40192421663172));
#1079=CARTESIAN_POINT('',(-4.20591017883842,14.7287268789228,5.27753720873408));
#1080=CARTESIAN_POINT('',(-3.83292493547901,14.8406399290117,6.21361174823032));
#1081=CARTESIAN_POINT('',(-3.06933568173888,15.037263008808,8.08136535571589));
#1082=CARTESIAN_POINT('',(-2.67873815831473,15.1219829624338,9.01304590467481));
#1083=CARTESIAN_POINT('',(-1.88037389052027,15.2615280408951,10.8716406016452));
#1084=CARTESIAN_POINT('',(-1.47260768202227,15.3163540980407,11.7985548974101));
#1085=CARTESIAN_POINT('',(-0.638270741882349,15.3932158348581,13.6519455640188));
#1086=CARTESIAN_POINT('',(-0.211607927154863,15.4150671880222,14.578390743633));
#1087=CARTESIAN_POINT('',(0.657441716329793,15.421761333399,16.4244134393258));
#1088=CARTESIAN_POINT('',(1.09982660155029,15.4066086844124,17.3439917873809));
#1089=CARTESIAN_POINT('',(2.00007345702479,15.3350094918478,19.1766864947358));
#1090=CARTESIAN_POINT('',(2.45796169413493,15.2784891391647,20.0897883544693));
#1091=CARTESIAN_POINT('',(3.15476073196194,15.1588826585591,21.4520277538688));
#1092=CARTESIAN_POINT('',(3.3887458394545,15.1131942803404,21.9049803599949));
#1093=CARTESIAN_POINT('',(3.85979797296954,15.0094522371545,22.8081040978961));
#1094=CARTESIAN_POINT('',(4.09686524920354,14.9513975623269,23.2582749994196));
#1095=CARTESIAN_POINT('',(4.33535141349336,14.8867874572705,23.7069006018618));
#1096=B_SPLINE_CURVE_WITH_KNOTS('',3,(#1054,#1055,#1056,#1057,#1058,#1059,#1060,#1061,#1062,
#1063,#1064,#1065,#1066,#1067,#1068,#1069,#1070,#1071,#1072,#1073,#1074,#1075,#1076,#1077,#1078,
#1079,#1080,#1081,#1082,#1083,#1084,#1085,#1086,#1087,#1088,#1089,#1090,#1091,#1092,#1093,#1094,
#1095),.UNSPECIFIED.,.F.,.F.,(4,2,2,2,2,2,2,2,2,2,2,2,2,2,2,2,2,2,2,2,4),(0.,2.15746623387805,
4.31494689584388,8.63044860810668,12.9390085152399,17.2470756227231,19.2268658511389,
21.2072723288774,25.352675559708,29.498174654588,33.6423071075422,37.7873618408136,
40.8203001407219,43.853282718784,46.8851571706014,49.9169370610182,52.9656024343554,
56.0138922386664,59.0676341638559,60.5952423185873,62.1229752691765),.UNSPECIFIED.);
#1097=EDGE_CURVE('E306',#831,#715,#1096,.T.);
#1098=ORIENTED_EDGE('',*,*,#1097,.T.);
#1099=ORIENTED_EDGE('',*,*,#716,.F.);
#1100=CARTESIAN_POINT('',(5.40021582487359,13.4775744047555,23.8506943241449));
#1101=CARTESIAN_POINT('',(5.1066455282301,13.5882540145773,23.2989984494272));
#1102=CARTESIAN_POINT('',(4.8148877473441,13.6873160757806,22.7443127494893));
#1103=CARTESIAN_POINT('',(4.23564024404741,13.863958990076,21.6298426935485));
#1104=CARTESIAN_POINT('',(3.94814966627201,13.9415442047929,21.0700593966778));
#1105=CARTESIAN_POINT('',(3.37824001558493,14.0769642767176,19.9466026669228));
#1106=CARTESIAN_POINT('',(3.09581623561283,14.1348184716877,19.3829335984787));
#1107=CARTESIAN_POINT('',(2.53618825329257,14.2323638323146,18.2517288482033));
#1108=CARTESIAN_POINT('',(2.25898434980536,14.2720539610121,17.684192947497));
#1109=CARTESIAN_POINT('',(1.43767962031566,14.3656937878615,15.9804635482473));
#1110=CARTESIAN_POINT('',(0.901885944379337,14.3946670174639,14.8392096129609));
#1111=CARTESIAN_POINT('',(-0.145168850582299,14.3947582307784,12.5461529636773));
#1112=CARTESIAN_POINT('',(-0.656422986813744,14.365859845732,11.3943473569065));
#1113=CARTESIAN_POINT('',(-1.64807812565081,14.2578945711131,9.09305656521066));
#1114=CARTESIAN_POINT('',(-2.12871788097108,14.1792873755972,7.9436459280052));
#1115=CARTESIAN_POINT('',(-3.06288450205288,13.9782238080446,5.6384052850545));
#1116=CARTESIAN_POINT('',(-3.51641356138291,13.8557709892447,4.48257580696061));
#1117=CARTESIAN_POINT('',(-4.39574590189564,13.5719327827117,2.1647843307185));
#1118=CARTESIAN_POINT('',(-4.82153004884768,13.4105208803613,1.00281868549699));
#1119=CARTESIAN_POINT('',(-5.64424747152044,13.0531683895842,-1.32549464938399));
#1120=CARTESIAN_POINT('',(-6.04118170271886,12.8572289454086,-2.49184219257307));
#1121=CARTESIAN_POINT('',(-6.80096326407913,12.437188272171,-4.81412457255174));
#1122=CARTESIAN_POINT('',(-7.16416384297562,12.2134550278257,-5.9700154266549));
#1123=CARTESIAN_POINT('',(-7.86112103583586,11.7393780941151,-8.28434888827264));
#1124=CARTESIAN_POINT('',(-8.19488872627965,11.4890444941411,-9.44279036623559));
#1125=CARTESIAN_POINT('',(-8.83278524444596,10.9644984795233,-11.7627013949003));
#1126=CARTESIAN_POINT('',(-9.13689995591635,10.6902748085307,-12.9241721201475));
#1127=CARTESIAN_POINT('',(-9.71482671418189,10.1206546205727,-15.2492153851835));
#1128=CARTESIAN_POINT('',(-9.98863708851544,9.82525693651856,-16.4127880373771));
#1129=CARTESIAN_POINT('',(-10.4959146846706,9.22677280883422,-18.6989327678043));
#1130=CARTESIAN_POINT('',(-10.730491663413,8.92436345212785,-19.8214468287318));
#1131=CARTESIAN_POINT('',(-11.1702905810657,8.30389578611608,-22.0673265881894));
#1132=CARTESIAN_POINT('',(-11.3755205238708,7.98584177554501,-23.1906919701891));
#1133=CARTESIAN_POINT('',(-11.6678382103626,7.48572996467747,-24.9184826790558));
#1134=CARTESIAN_POINT('',(-11.7656723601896,7.30879528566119,-25.5226635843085));
#1135=CARTESIAN_POINT('',(-11.9523876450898,6.950858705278,-26.7311652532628));
#1136=CARTESIAN_POINT('',(-12.041268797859,6.76985681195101,-27.3354860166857));
#1137=CARTESIAN_POINT('',(-12.2098250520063,6.40376772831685,-28.5443476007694));
#1138=CARTESIAN_POINT('',(-12.2894975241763,6.21867938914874,-29.1488884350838));
#1139=CARTESIAN_POINT('',(-12.4391462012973,5.84425664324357,-30.3578893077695));
#1140=CARTESIAN_POINT('',(-12.5091224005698,5.65492223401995,-30.9623493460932));
#1141=CARTESIAN_POINT('',(-12.5740199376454,5.46335959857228,-31.56670425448));
#1142=B_SPLINE_CURVE_WITH_KNOTS('',3,(#1100,#1101,#1102,#1103,#1104,#1105,#1106,#1107,#1108,
#1109,#1110,#1111,#1112,#1113,#1114,#1115,#1116,#1117,#1118,#1119,#1120,#1121,#1122,#1123,#1124,
#1125,#1126,#1127,#1128,#1129,#1130,#1131,#1132,#1133,#1134,#1135,#1136,#1137,#1138,#1139,#1140,
#1141),.UNSPECIFIED.,.F.,.F.,(4,2,2,2,2,2,2,2,2,2,2,2,2,2,2,2,2,2,2,2,4),(0.,1.89213037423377,
3.78387620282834,5.67376262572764,7.56375692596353,11.3305099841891,15.0983286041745,
18.8318030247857,22.564974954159,26.3006947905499,30.0362908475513,33.7268520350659,
37.4160183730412,41.1069324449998,44.7980501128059,48.3540759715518,51.9091301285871,
53.8202498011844,55.7313656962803,57.6430259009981,59.5546872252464),.UNSPECIFIED.);
#1143=EDGE_CURVE('E338',#706,#840,#1142,.T.);
#1144=ORIENTED_EDGE('',*,*,#1143,.T.);
#1145=EDGE_LOOP('',(#1053,#1098,#1099,#1144));
#1146=FACE_BOUND('',#1145,.T.);
#1147=ADVANCED_FACE('F244',(#1146),#1052,.T.);
#1148=CARTESIAN_POINT('',(-17.,-5.90349216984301,-22.));
#1149=DIRECTION('',(0.,0.866025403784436,-0.500000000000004));
#1150=DIRECTION('',(0.,0.500000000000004,0.866025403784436));
#1151=AXIS2_PLACEMENT_3D('',#1148,#1149,#1150);
#1152=PLANE('',#1151);
#1153=ORIENTED_EDGE('',*,*,#951,.F.);
#1154=CARTESIAN_POINT('',(-12.8904871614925,-2.76497449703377,-16.5639279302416));
#1155=DIRECTION('',(0.,0.866025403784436,-0.500000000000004));
#1156=DIRECTION('',(0.,0.500000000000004,0.866025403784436));
#1157=AXIS2_PLACEMENT_3D('',#1154,#1155,#1156);
#1158=ELLIPSE('',#1157,5.99999999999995,3.);
#1159=EDGE_CURVE('E376',#941,#610,#1158,.F.);
#1160=ORIENTED_EDGE('',*,*,#1159,.T.);
#1161=ORIENTED_EDGE('',*,*,#611,.T.);
#1162=ORIENTED_EDGE('',*,*,#587,.F.);
#1163=CARTESIAN_POINT('',(-9.39203373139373,-2.61767117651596,-16.3087910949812));
#1164=DIRECTION('',(0.,0.866025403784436,-0.500000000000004));
#1165=DIRECTION('',(0.,-0.500000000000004,-0.866025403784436));
#1166=AXIS2_PLACEMENT_3D('',#1163,#1164,#1165);
#1167=ELLIPSE('',#1166,5.99999999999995,3.);
#1168=EDGE_CURVE('E11',#582,#918,#1167,.T.);
#1169=ORIENTED_EDGE('',*,*,#1168,.T.);
#1170=ORIENTED_EDGE('',*,*,#919,.F.);
#1171=CARTESIAN_POINT('',(-9.39203373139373,2.61767117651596,-7.24091214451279));
#1172=DIRECTION('',(0.,0.866025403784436,-0.500000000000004));
#1173=DIRECTION('',(0.,-0.500000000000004,-0.866025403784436));
#1174=AXIS2_PLACEMENT_3D('',#1171,#1172,#1173);
#1175=ELLIPSE('',#1174,5.99999999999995,3.);
#1176=EDGE_CURVE('E56',#910,#32,#1175,.T.);
#1177=ORIENTED_EDGE('',*,*,#1176,.T.);
#1178=ORIENTED_EDGE('',*,*,#33,.F.);
#1179=ORIENTED_EDGE('',*,*,#664,.F.);
#1180=ORIENTED_EDGE('',*,*,#368,.T.);
#1181=CARTESIAN_POINT('',(-17.578125,6.52472386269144,-0.473698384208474));
#1182=DIRECTION('',(0.,0.866025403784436,-0.500000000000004));
#1183=DIRECTION('',(0.,0.500000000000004,0.866025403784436));
#1184=AXIS2_PLACEMENT_3D('',#1181,#1182,#1183);
#1185=ELLIPSE('',#1184,5.99999999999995,3.);
#1186=EDGE_CURVE('E390',#358,#950,#1185,.T.);
#1187=ORIENTED_EDGE('',*,*,#1186,.T.);
#1188=EDGE_LOOP('',(#1153,#1160,#1161,#1162,#1169,#1170,#1177,#1178,#1179,#1180,#1187));
#1189=FACE_BOUND('',#1188,.T.);
#1190=ORIENTED_EDGE('',*,*,#974,.T.);
#1191=EDGE_LOOP('',(#1190));
#1192=FACE_BOUND('',#1191,.T.);
#1193=ADVANCED_FACE('F161',(#1189,#1192),#1152,.F.);
#1194=ORIENTED_EDGE('',*,*,#737,.F.);
#1195=ORIENTED_EDGE('',*,*,#1097,.F.);
#1196=ORIENTED_EDGE('',*,*,#832,.F.);
#1197=ORIENTED_EDGE('',*,*,#566,.F.);
#1198=EDGE_LOOP('',(#1194,#1195,#1196,#1197));
#1199=FACE_BOUND('',#1198,.T.);
#1200=ADVANCED_FACE('F247',(#1199),#522,.T.);
#1201=ORIENTED_EDGE('',*,*,#868,.F.);
#1202=ORIENTED_EDGE('',*,*,#1143,.F.);
#1203=ORIENTED_EDGE('',*,*,#707,.F.);
#1204=ORIENTED_EDGE('',*,*,#308,.F.);
#1205=EDGE_LOOP('',(#1201,#1202,#1203,#1204));
#1206=FACE_BOUND('',#1205,.T.);
#1207=ADVANCED_FACE('F253',(#1206),#262,.T.);
#1208=CARTESIAN_POINT('',(-12.8904871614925,-2.76497449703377,2.));
#1209=DIRECTION('',(0.,0.,1.));
#1210=DIRECTION('',(1.,0.,0.));
#1211=AXIS2_PLACEMENT_3D('',#1208,#1209,#1210);
#1212=CYLINDRICAL_SURFACE('',#1211,3.);
#1213=ORIENTED_EDGE('',*,*,#1159,.F.);
#1214=ORIENTED_EDGE('',*,*,#942,.F.);
#1215=ORIENTED_EDGE('',*,*,#790,.F.);
#1216=ORIENTED_EDGE('',*,*,#619,.F.);
#1217=EDGE_LOOP('',(#1213,#1214,#1215,#1216));
#1218=FACE_BOUND('',#1217,.T.);
#1219=ADVANCED_FACE('F286',(#1218),#1212,.T.);
#1220=CARTESIAN_POINT('',(-17.578125,6.52472386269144,4.));
#1221=DIRECTION('',(0.,0.,1.));
#1222=DIRECTION('',(1.,0.,0.));
#1223=AXIS2_PLACEMENT_3D('',#1220,#1221,#1222);
#1224=CYLINDRICAL_SURFACE('',#1223,3.);
#1225=ORIENTED_EDGE('',*,*,#1186,.F.);
#1226=ORIENTED_EDGE('',*,*,#359,.F.);
#1227=ORIENTED_EDGE('',*,*,#806,.F.);
#1228=ORIENTED_EDGE('',*,*,#957,.F.);
#1229=EDGE_LOOP('',(#1225,#1226,#1227,#1228));
#1230=FACE_BOUND('',#1229,.T.);
#1231=ADVANCED_FACE('F446',(#1230),#1224,.F.);
#1232=CARTESIAN_POINT('',(-9.39203373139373,2.61767117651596,4.));
#1233=DIRECTION('',(0.,0.,-1.));
#1234=DIRECTION('',(-1.,0.,0.));
#1235=AXIS2_PLACEMENT_3D('',#1232,#1233,#1234);
#1236=CYLINDRICAL_SURFACE('',#1235,3.);
#1237=ORIENTED_EDGE('',*,*,#1176,.F.);
#1238=ORIENTED_EDGE('',*,*,#911,.F.);
#1239=ORIENTED_EDGE('',*,*,#878,.F.);
#1240=ORIENTED_EDGE('',*,*,#41,.F.);
#1241=EDGE_LOOP('',(#1237,#1238,#1239,#1240));
#1242=FACE_BOUND('',#1241,.T.);
#1243=ADVANCED_FACE('F448',(#1242),#1236,.F.);
#1244=CARTESIAN_POINT('',(-9.39203373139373,-2.61767117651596,4.));
#1245=DIRECTION('',(0.,0.,-1.));
#1246=DIRECTION('',(-1.,0.,0.));
#1247=AXIS2_PLACEMENT_3D('',#1244,#1245,#1246);
#1248=CYLINDRICAL_SURFACE('',#1247,3.);
#1249=ORIENTED_EDGE('',*,*,#1168,.F.);
#1250=ORIENTED_EDGE('',*,*,#583,.F.);
#1251=ORIENTED_EDGE('',*,*,#893,.F.);
#1252=ORIENTED_EDGE('',*,*,#925,.F.);
#1253=EDGE_LOOP('',(#1249,#1250,#1251,#1252));
#1254=FACE_BOUND('',#1253,.T.);
#1255=ADVANCED_FACE('F43',(#1254),#1248,.F.);
#1256=CLOSED_SHELL('',(#336,#570,#597,#630,#654,#671,#743,#898,#929,#961,#981,#1002,#1014,#1035,
#1047,#1147,#1193,#1200,#1207,#1219,#1231,#1243,#1255));
#1257=MANIFOLD_SOLID_BREP('B2',#1256);
#1258=ADVANCED_BREP_SHAPE_REPRESENTATION('',(#18,#1257),#14);
#1259=SHAPE_DEFINITION_REPRESENTATION(#9,#1258);
ENDSEC;
END-ISO-10303-21;
